VERSION 5.7 ;
  NOWIREEXTENSIONATPIN ON ;
  DIVIDERCHAR "/" ;
  BUSBITCHARS "[]" ;
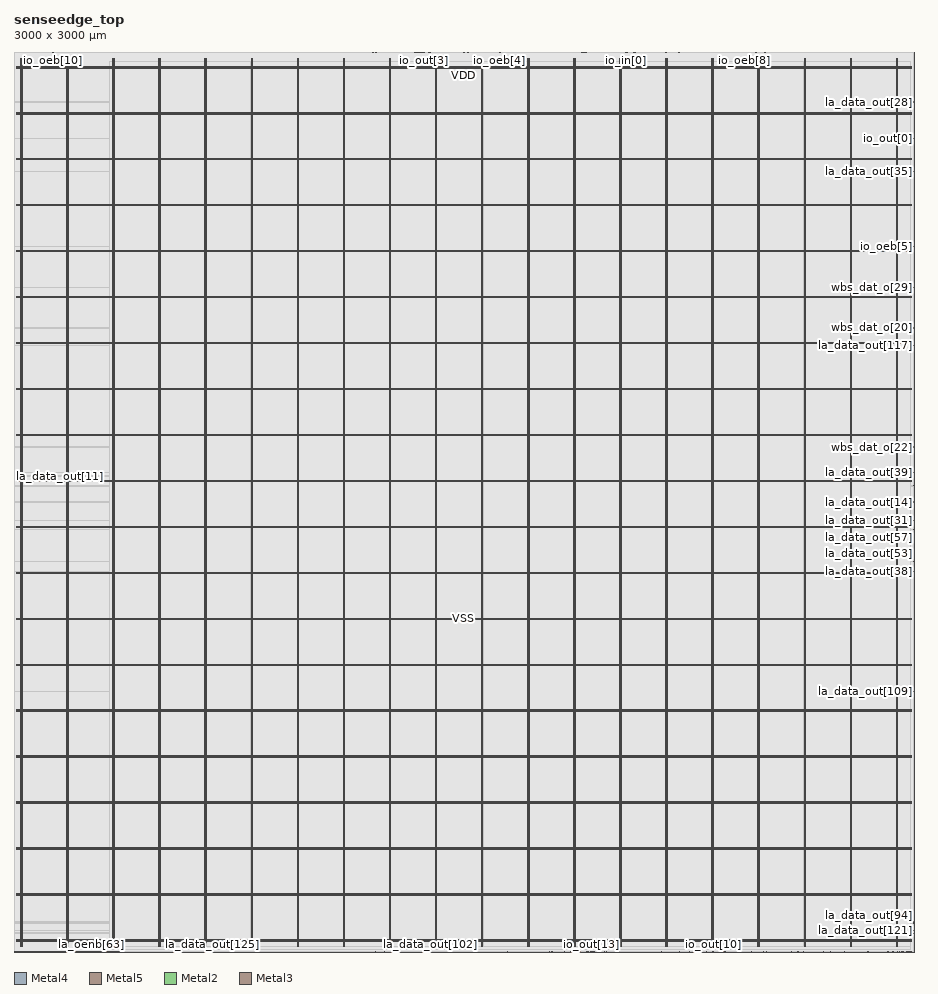
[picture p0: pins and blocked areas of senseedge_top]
MACRO senseedge_top
  CLASS BLOCK ;
  FOREIGN senseedge_top ;
  ORIGIN 0.000 0.000 ;
  SIZE 3000.000 BY 3000.000 ;
  PIN VDD
    DIRECTION INOUT ;
    USE POWER ;
    PORT
      LAYER Metal4 ;
        RECT 22.240 19.860 23.840 2978.940 ;
    END
    PORT
      LAYER Metal4 ;
        RECT 175.840 19.860 177.440 2978.940 ;
    END
    PORT
      LAYER Metal4 ;
        RECT 329.440 19.860 331.040 2978.940 ;
    END
    PORT
      LAYER Metal4 ;
        RECT 483.040 19.860 484.640 2978.940 ;
    END
    PORT
      LAYER Metal4 ;
        RECT 636.640 19.860 638.240 2978.940 ;
    END
    PORT
      LAYER Metal4 ;
        RECT 790.240 19.860 791.840 2978.940 ;
    END
    PORT
      LAYER Metal4 ;
        RECT 943.840 19.860 945.440 2978.940 ;
    END
    PORT
      LAYER Metal4 ;
        RECT 1097.440 19.860 1099.040 2978.940 ;
    END
    PORT
      LAYER Metal4 ;
        RECT 1251.040 19.860 1252.640 2978.940 ;
    END
    PORT
      LAYER Metal4 ;
        RECT 1404.640 19.860 1406.240 2978.940 ;
    END
    PORT
      LAYER Metal4 ;
        RECT 1558.240 19.860 1559.840 2978.940 ;
    END
    PORT
      LAYER Metal4 ;
        RECT 1711.840 19.860 1713.440 2978.940 ;
    END
    PORT
      LAYER Metal4 ;
        RECT 1865.440 19.860 1867.040 2978.940 ;
    END
    PORT
      LAYER Metal4 ;
        RECT 2019.040 19.860 2020.640 2978.940 ;
    END
    PORT
      LAYER Metal4 ;
        RECT 2172.640 19.860 2174.240 2978.940 ;
    END
    PORT
      LAYER Metal4 ;
        RECT 2326.240 19.860 2327.840 2978.940 ;
    END
    PORT
      LAYER Metal4 ;
        RECT 2479.840 19.860 2481.440 2978.940 ;
    END
    PORT
      LAYER Metal4 ;
        RECT 2633.440 19.860 2635.040 2978.940 ;
    END
    PORT
      LAYER Metal4 ;
        RECT 2787.040 19.860 2788.640 2978.940 ;
    END
    PORT
      LAYER Metal4 ;
        RECT 2940.640 19.860 2942.240 2978.940 ;
    END
    PORT
      LAYER Metal5 ;
        RECT 6.720 36.010 2993.200 37.610 ;
    END
    PORT
      LAYER Metal5 ;
        RECT 6.720 189.190 2993.200 190.790 ;
    END
    PORT
      LAYER Metal5 ;
        RECT 6.720 342.370 2993.200 343.970 ;
    END
    PORT
      LAYER Metal5 ;
        RECT 6.720 495.550 2993.200 497.150 ;
    END
    PORT
      LAYER Metal5 ;
        RECT 6.720 648.730 2993.200 650.330 ;
    END
    PORT
      LAYER Metal5 ;
        RECT 6.720 801.910 2993.200 803.510 ;
    END
    PORT
      LAYER Metal5 ;
        RECT 6.720 955.090 2993.200 956.690 ;
    END
    PORT
      LAYER Metal5 ;
        RECT 6.720 1108.270 2993.200 1109.870 ;
    END
    PORT
      LAYER Metal5 ;
        RECT 6.720 1261.450 2993.200 1263.050 ;
    END
    PORT
      LAYER Metal5 ;
        RECT 6.720 1414.630 2993.200 1416.230 ;
    END
    PORT
      LAYER Metal5 ;
        RECT 6.720 1567.810 2993.200 1569.410 ;
    END
    PORT
      LAYER Metal5 ;
        RECT 6.720 1720.990 2993.200 1722.590 ;
    END
    PORT
      LAYER Metal5 ;
        RECT 6.720 1874.170 2993.200 1875.770 ;
    END
    PORT
      LAYER Metal5 ;
        RECT 6.720 2027.350 2993.200 2028.950 ;
    END
    PORT
      LAYER Metal5 ;
        RECT 6.720 2180.530 2993.200 2182.130 ;
    END
    PORT
      LAYER Metal5 ;
        RECT 6.720 2333.710 2993.200 2335.310 ;
    END
    PORT
      LAYER Metal5 ;
        RECT 6.720 2486.890 2993.200 2488.490 ;
    END
    PORT
      LAYER Metal5 ;
        RECT 6.720 2640.070 2993.200 2641.670 ;
    END
    PORT
      LAYER Metal5 ;
        RECT 6.720 2793.250 2993.200 2794.850 ;
    END
    PORT
      LAYER Metal5 ;
        RECT 6.720 2946.430 2993.200 2948.030 ;
    END
  END VDD
  PIN VSS
    DIRECTION INOUT ;
    USE GROUND ;
    PORT
      LAYER Metal4 ;
        RECT 25.540 19.860 27.140 2978.940 ;
    END
    PORT
      LAYER Metal4 ;
        RECT 179.140 19.860 180.740 2978.940 ;
    END
    PORT
      LAYER Metal4 ;
        RECT 332.740 19.860 334.340 2978.940 ;
    END
    PORT
      LAYER Metal4 ;
        RECT 486.340 19.860 487.940 2978.940 ;
    END
    PORT
      LAYER Metal4 ;
        RECT 639.940 19.860 641.540 2978.940 ;
    END
    PORT
      LAYER Metal4 ;
        RECT 793.540 19.860 795.140 2978.940 ;
    END
    PORT
      LAYER Metal4 ;
        RECT 947.140 19.860 948.740 2978.940 ;
    END
    PORT
      LAYER Metal4 ;
        RECT 1100.740 19.860 1102.340 2978.940 ;
    END
    PORT
      LAYER Metal4 ;
        RECT 1254.340 19.860 1255.940 2978.940 ;
    END
    PORT
      LAYER Metal4 ;
        RECT 1407.940 19.860 1409.540 2978.940 ;
    END
    PORT
      LAYER Metal4 ;
        RECT 1561.540 19.860 1563.140 2978.940 ;
    END
    PORT
      LAYER Metal4 ;
        RECT 1715.140 19.860 1716.740 2978.940 ;
    END
    PORT
      LAYER Metal4 ;
        RECT 1868.740 19.860 1870.340 2978.940 ;
    END
    PORT
      LAYER Metal4 ;
        RECT 2022.340 19.860 2023.940 2978.940 ;
    END
    PORT
      LAYER Metal4 ;
        RECT 2175.940 19.860 2177.540 2978.940 ;
    END
    PORT
      LAYER Metal4 ;
        RECT 2329.540 19.860 2331.140 2978.940 ;
    END
    PORT
      LAYER Metal4 ;
        RECT 2483.140 19.860 2484.740 2978.940 ;
    END
    PORT
      LAYER Metal4 ;
        RECT 2636.740 19.860 2638.340 2978.940 ;
    END
    PORT
      LAYER Metal4 ;
        RECT 2790.340 19.860 2791.940 2978.940 ;
    END
    PORT
      LAYER Metal4 ;
        RECT 2943.940 19.860 2945.540 2978.940 ;
    END
    PORT
      LAYER Metal5 ;
        RECT 6.720 39.310 2993.200 40.910 ;
    END
    PORT
      LAYER Metal5 ;
        RECT 6.720 192.490 2993.200 194.090 ;
    END
    PORT
      LAYER Metal5 ;
        RECT 6.720 345.670 2993.200 347.270 ;
    END
    PORT
      LAYER Metal5 ;
        RECT 6.720 498.850 2993.200 500.450 ;
    END
    PORT
      LAYER Metal5 ;
        RECT 6.720 652.030 2993.200 653.630 ;
    END
    PORT
      LAYER Metal5 ;
        RECT 6.720 805.210 2993.200 806.810 ;
    END
    PORT
      LAYER Metal5 ;
        RECT 6.720 958.390 2993.200 959.990 ;
    END
    PORT
      LAYER Metal5 ;
        RECT 6.720 1111.570 2993.200 1113.170 ;
    END
    PORT
      LAYER Metal5 ;
        RECT 6.720 1264.750 2993.200 1266.350 ;
    END
    PORT
      LAYER Metal5 ;
        RECT 6.720 1417.930 2993.200 1419.530 ;
    END
    PORT
      LAYER Metal5 ;
        RECT 6.720 1571.110 2993.200 1572.710 ;
    END
    PORT
      LAYER Metal5 ;
        RECT 6.720 1724.290 2993.200 1725.890 ;
    END
    PORT
      LAYER Metal5 ;
        RECT 6.720 1877.470 2993.200 1879.070 ;
    END
    PORT
      LAYER Metal5 ;
        RECT 6.720 2030.650 2993.200 2032.250 ;
    END
    PORT
      LAYER Metal5 ;
        RECT 6.720 2183.830 2993.200 2185.430 ;
    END
    PORT
      LAYER Metal5 ;
        RECT 6.720 2337.010 2993.200 2338.610 ;
    END
    PORT
      LAYER Metal5 ;
        RECT 6.720 2490.190 2993.200 2491.790 ;
    END
    PORT
      LAYER Metal5 ;
        RECT 6.720 2643.370 2993.200 2644.970 ;
    END
    PORT
      LAYER Metal5 ;
        RECT 6.720 2796.550 2993.200 2798.150 ;
    END
    PORT
      LAYER Metal5 ;
        RECT 6.720 2949.730 2993.200 2951.330 ;
    END
  END VSS
  PIN io_in[0]
    DIRECTION INPUT ;
    USE SIGNAL ;
    ANTENNAGATEAREA 0.396000 ;
    PORT
      LAYER Metal2 ;
        RECT 2039.520 2999.440 2040.080 3000.000 ;
    END
  END io_in[0]
  PIN io_in[10]
    DIRECTION INPUT ;
    USE SIGNAL ;
    PORT
      LAYER Metal2 ;
        RECT 1.120 0.000 1.680 0.560 ;
    END
  END io_in[10]
  PIN io_in[11]
    DIRECTION INPUT ;
    USE SIGNAL ;
    PORT
      LAYER Metal2 ;
        RECT 2.240 0.000 2.800 0.560 ;
    END
  END io_in[11]
  PIN io_in[12]
    DIRECTION INPUT ;
    USE SIGNAL ;
    PORT
      LAYER Metal2 ;
        RECT 3.360 0.000 3.920 0.560 ;
    END
  END io_in[12]
  PIN io_in[13]
    DIRECTION INPUT ;
    USE SIGNAL ;
    PORT
      LAYER Metal2 ;
        RECT 4.480 0.000 5.040 0.560 ;
    END
  END io_in[13]
  PIN io_in[14]
    DIRECTION INPUT ;
    USE SIGNAL ;
    PORT
      LAYER Metal2 ;
        RECT 5.600 0.000 6.160 0.560 ;
    END
  END io_in[14]
  PIN io_in[15]
    DIRECTION INPUT ;
    USE SIGNAL ;
    PORT
      LAYER Metal2 ;
        RECT 6.720 0.000 7.280 0.560 ;
    END
  END io_in[15]
  PIN io_in[1]
    DIRECTION INPUT ;
    USE SIGNAL ;
    PORT
      LAYER Metal2 ;
        RECT 7.840 0.000 8.400 0.560 ;
    END
  END io_in[1]
  PIN io_in[2]
    DIRECTION INPUT ;
    USE SIGNAL ;
    PORT
      LAYER Metal2 ;
        RECT 8.960 0.000 9.520 0.560 ;
    END
  END io_in[2]
  PIN io_in[3]
    DIRECTION INPUT ;
    USE SIGNAL ;
    PORT
      LAYER Metal2 ;
        RECT 10.080 0.000 10.640 0.560 ;
    END
  END io_in[3]
  PIN io_in[4]
    DIRECTION INPUT ;
    USE SIGNAL ;
    PORT
      LAYER Metal2 ;
        RECT 11.200 0.000 11.760 0.560 ;
    END
  END io_in[4]
  PIN io_in[5]
    DIRECTION INPUT ;
    USE SIGNAL ;
    PORT
      LAYER Metal2 ;
        RECT 12.320 0.000 12.880 0.560 ;
    END
  END io_in[5]
  PIN io_in[6]
    DIRECTION INPUT ;
    USE SIGNAL ;
    PORT
      LAYER Metal2 ;
        RECT 13.440 0.000 14.000 0.560 ;
    END
  END io_in[6]
  PIN io_in[7]
    DIRECTION INPUT ;
    USE SIGNAL ;
    PORT
      LAYER Metal2 ;
        RECT 14.560 0.000 15.120 0.560 ;
    END
  END io_in[7]
  PIN io_in[8]
    DIRECTION INPUT ;
    USE SIGNAL ;
    PORT
      LAYER Metal2 ;
        RECT 15.680 0.000 16.240 0.560 ;
    END
  END io_in[8]
  PIN io_in[9]
    DIRECTION INPUT ;
    USE SIGNAL ;
    PORT
      LAYER Metal2 ;
        RECT 16.800 0.000 17.360 0.560 ;
    END
  END io_in[9]
  PIN io_oeb[0]
    DIRECTION OUTPUT ;
    USE SIGNAL ;
    ANTENNADIFFAREA 0.396000 ;
    PORT
      LAYER Metal2 ;
        RECT 2251.200 0.000 2251.760 0.560 ;
    END
  END io_oeb[0]
  PIN io_oeb[10]
    DIRECTION OUTPUT ;
    USE SIGNAL ;
    ANTENNADIFFAREA 0.396000 ;
    PORT
      LAYER Metal2 ;
        RECT 129.920 2999.440 130.480 3000.000 ;
    END
  END io_oeb[10]
  PIN io_oeb[11]
    DIRECTION OUTPUT ;
    USE SIGNAL ;
    ANTENNADIFFAREA 0.396000 ;
    PORT
      LAYER Metal2 ;
        RECT 1933.120 0.000 1933.680 0.560 ;
    END
  END io_oeb[11]
  PIN io_oeb[12]
    DIRECTION OUTPUT ;
    USE SIGNAL ;
    ANTENNADIFFAREA 0.396000 ;
    PORT
      LAYER Metal2 ;
        RECT 2117.920 2999.440 2118.480 3000.000 ;
    END
  END io_oeb[12]
  PIN io_oeb[13]
    DIRECTION OUTPUT ;
    USE SIGNAL ;
    ANTENNADIFFAREA 0.396000 ;
    PORT
      LAYER Metal2 ;
        RECT 1911.840 0.000 1912.400 0.560 ;
    END
  END io_oeb[13]
  PIN io_oeb[14]
    DIRECTION OUTPUT ;
    USE SIGNAL ;
    ANTENNADIFFAREA 0.396000 ;
    PORT
      LAYER Metal3 ;
        RECT 2999.440 62.720 3000.000 63.280 ;
    END
  END io_oeb[14]
  PIN io_oeb[15]
    DIRECTION OUTPUT ;
    USE SIGNAL ;
    ANTENNADIFFAREA 0.396000 ;
    PORT
      LAYER Metal2 ;
        RECT 2391.200 2999.440 2391.760 3000.000 ;
    END
  END io_oeb[15]
  PIN io_oeb[1]
    DIRECTION OUTPUT ;
    USE SIGNAL ;
    ANTENNADIFFAREA 0.290400 ;
    PORT
      LAYER Metal2 ;
        RECT 2051.840 2999.440 2052.400 3000.000 ;
    END
  END io_oeb[1]
  PIN io_oeb[2]
    DIRECTION OUTPUT ;
    USE SIGNAL ;
    ANTENNADIFFAREA 0.290400 ;
    PORT
      LAYER Metal2 ;
        RECT 2973.600 0.000 2974.160 0.560 ;
    END
  END io_oeb[2]
  PIN io_oeb[3]
    DIRECTION OUTPUT ;
    USE SIGNAL ;
    ANTENNADIFFAREA 0.290400 ;
    PORT
      LAYER Metal2 ;
        RECT 2115.680 2999.440 2116.240 3000.000 ;
    END
  END io_oeb[3]
  PIN io_oeb[4]
    DIRECTION OUTPUT ;
    USE SIGNAL ;
    ANTENNADIFFAREA 0.290400 ;
    PORT
      LAYER Metal2 ;
        RECT 1617.280 2999.440 1617.840 3000.000 ;
    END
  END io_oeb[4]
  PIN io_oeb[5]
    DIRECTION OUTPUT ;
    USE SIGNAL ;
    ANTENNADIFFAREA 0.290400 ;
    PORT
      LAYER Metal3 ;
        RECT 2999.440 2352.000 3000.000 2352.560 ;
    END
  END io_oeb[5]
  PIN io_oeb[6]
    DIRECTION OUTPUT ;
    USE SIGNAL ;
    ANTENNADIFFAREA 0.396000 ;
    PORT
      LAYER Metal2 ;
        RECT 2042.880 2999.440 2043.440 3000.000 ;
    END
  END io_oeb[6]
  PIN io_oeb[7]
    DIRECTION OUTPUT ;
    USE SIGNAL ;
    ANTENNADIFFAREA 0.396000 ;
    PORT
      LAYER Metal2 ;
        RECT 2951.200 0.000 2951.760 0.560 ;
    END
  END io_oeb[7]
  PIN io_oeb[8]
    DIRECTION OUTPUT ;
    USE SIGNAL ;
    ANTENNADIFFAREA 0.396000 ;
    PORT
      LAYER Metal2 ;
        RECT 2434.880 2999.440 2435.440 3000.000 ;
    END
  END io_oeb[8]
  PIN io_oeb[9]
    DIRECTION OUTPUT ;
    USE SIGNAL ;
    ANTENNADIFFAREA 0.396000 ;
    PORT
      LAYER Metal2 ;
        RECT 1972.320 2999.440 1972.880 3000.000 ;
    END
  END io_oeb[9]
  PIN io_out[0]
    DIRECTION OUTPUT ;
    USE SIGNAL ;
    ANTENNADIFFAREA 0.290400 ;
    PORT
      LAYER Metal3 ;
        RECT 2999.440 2711.520 3000.000 2712.080 ;
    END
  END io_out[0]
  PIN io_out[10]
    DIRECTION OUTPUT ;
    USE SIGNAL ;
    ANTENNADIFFAREA 0.290400 ;
    PORT
      LAYER Metal2 ;
        RECT 2331.840 0.000 2332.400 0.560 ;
    END
  END io_out[10]
  PIN io_out[11]
    DIRECTION OUTPUT ;
    USE SIGNAL ;
    ANTENNADIFFAREA 0.290400 ;
    PORT
      LAYER Metal2 ;
        RECT 2294.880 2999.440 2295.440 3000.000 ;
    END
  END io_out[11]
  PIN io_out[12]
    DIRECTION OUTPUT ;
    USE SIGNAL ;
    ANTENNADIFFAREA 0.290400 ;
    PORT
      LAYER Metal2 ;
        RECT 2157.120 0.000 2157.680 0.560 ;
    END
  END io_out[12]
  PIN io_out[13]
    DIRECTION OUTPUT ;
    USE SIGNAL ;
    ANTENNADIFFAREA 0.290400 ;
    PORT
      LAYER Metal2 ;
        RECT 1924.160 0.000 1924.720 0.560 ;
    END
  END io_out[13]
  PIN io_out[14]
    DIRECTION OUTPUT ;
    USE SIGNAL ;
    ANTENNADIFFAREA 0.290400 ;
    PORT
      LAYER Metal2 ;
        RECT 1888.320 0.000 1888.880 0.560 ;
    END
  END io_out[14]
  PIN io_out[15]
    DIRECTION OUTPUT ;
    USE SIGNAL ;
    ANTENNADIFFAREA 0.290400 ;
    PORT
      LAYER Metal2 ;
        RECT 1785.280 0.000 1785.840 0.560 ;
    END
  END io_out[15]
  PIN io_out[1]
    DIRECTION OUTPUT ;
    USE SIGNAL ;
    ANTENNADIFFAREA 1.386000 ;
    PORT
      LAYER Metal2 ;
        RECT 1681.120 2999.440 1681.680 3000.000 ;
    END
  END io_out[1]
  PIN io_out[2]
    DIRECTION OUTPUT ;
    USE SIGNAL ;
    ANTENNADIFFAREA 1.386000 ;
    PORT
      LAYER Metal2 ;
        RECT 1680.000 2999.440 1680.560 3000.000 ;
    END
  END io_out[2]
  PIN io_out[3]
    DIRECTION OUTPUT ;
    USE SIGNAL ;
    ANTENNADIFFAREA 1.386000 ;
    PORT
      LAYER Metal2 ;
        RECT 1365.280 2999.440 1365.840 3000.000 ;
    END
  END io_out[3]
  PIN io_out[4]
    DIRECTION OUTPUT ;
    USE SIGNAL ;
    ANTENNADIFFAREA 1.386000 ;
    PORT
      LAYER Metal2 ;
        RECT 1364.160 2999.440 1364.720 3000.000 ;
    END
  END io_out[4]
  PIN io_out[5]
    DIRECTION OUTPUT ;
    USE SIGNAL ;
    ANTENNADIFFAREA 0.396000 ;
    PORT
      LAYER Metal2 ;
        RECT 2698.080 0.000 2698.640 0.560 ;
    END
  END io_out[5]
  PIN io_out[6]
    DIRECTION OUTPUT ;
    USE SIGNAL ;
    ANTENNADIFFAREA 0.290400 ;
    PORT
      LAYER Metal2 ;
        RECT 2979.200 0.000 2979.760 0.560 ;
    END
  END io_out[6]
  PIN io_out[7]
    DIRECTION OUTPUT ;
    USE SIGNAL ;
    ANTENNADIFFAREA 0.290400 ;
    PORT
      LAYER Metal2 ;
        RECT 1974.560 0.000 1975.120 0.560 ;
    END
  END io_out[7]
  PIN io_out[8]
    DIRECTION OUTPUT ;
    USE SIGNAL ;
    ANTENNADIFFAREA 0.290400 ;
    PORT
      LAYER Metal2 ;
        RECT 2508.800 0.000 2509.360 0.560 ;
    END
  END io_out[8]
  PIN io_out[9]
    DIRECTION OUTPUT ;
    USE SIGNAL ;
    ANTENNADIFFAREA 0.290400 ;
    PORT
      LAYER Metal2 ;
        RECT 2990.400 0.000 2990.960 0.560 ;
    END
  END io_out[9]
  PIN irq[0]
    DIRECTION OUTPUT ;
    USE SIGNAL ;
    ANTENNADIFFAREA 1.386000 ;
    PORT
      LAYER Metal2 ;
        RECT 1344.000 2999.440 1344.560 3000.000 ;
    END
  END irq[0]
  PIN irq[1]
    DIRECTION OUTPUT ;
    USE SIGNAL ;
    ANTENNADIFFAREA 0.290400 ;
    PORT
      LAYER Metal2 ;
        RECT 1725.920 2999.440 1726.480 3000.000 ;
    END
  END irq[1]
  PIN irq[2]
    DIRECTION OUTPUT ;
    USE SIGNAL ;
    ANTENNADIFFAREA 0.290400 ;
    PORT
      LAYER Metal2 ;
        RECT 2985.920 0.000 2986.480 0.560 ;
    END
  END irq[2]
  PIN la_data_in[0]
    DIRECTION INPUT ;
    USE SIGNAL ;
    PORT
      LAYER Metal2 ;
        RECT 17.920 0.000 18.480 0.560 ;
    END
  END la_data_in[0]
  PIN la_data_in[100]
    DIRECTION INPUT ;
    USE SIGNAL ;
    PORT
      LAYER Metal2 ;
        RECT 19.040 0.000 19.600 0.560 ;
    END
  END la_data_in[100]
  PIN la_data_in[101]
    DIRECTION INPUT ;
    USE SIGNAL ;
    PORT
      LAYER Metal2 ;
        RECT 20.160 0.000 20.720 0.560 ;
    END
  END la_data_in[101]
  PIN la_data_in[102]
    DIRECTION INPUT ;
    USE SIGNAL ;
    PORT
      LAYER Metal2 ;
        RECT 21.280 0.000 21.840 0.560 ;
    END
  END la_data_in[102]
  PIN la_data_in[103]
    DIRECTION INPUT ;
    USE SIGNAL ;
    PORT
      LAYER Metal2 ;
        RECT 22.400 0.000 22.960 0.560 ;
    END
  END la_data_in[103]
  PIN la_data_in[104]
    DIRECTION INPUT ;
    USE SIGNAL ;
    PORT
      LAYER Metal2 ;
        RECT 23.520 0.000 24.080 0.560 ;
    END
  END la_data_in[104]
  PIN la_data_in[105]
    DIRECTION INPUT ;
    USE SIGNAL ;
    PORT
      LAYER Metal2 ;
        RECT 24.640 0.000 25.200 0.560 ;
    END
  END la_data_in[105]
  PIN la_data_in[106]
    DIRECTION INPUT ;
    USE SIGNAL ;
    PORT
      LAYER Metal2 ;
        RECT 25.760 0.000 26.320 0.560 ;
    END
  END la_data_in[106]
  PIN la_data_in[107]
    DIRECTION INPUT ;
    USE SIGNAL ;
    PORT
      LAYER Metal2 ;
        RECT 26.880 0.000 27.440 0.560 ;
    END
  END la_data_in[107]
  PIN la_data_in[108]
    DIRECTION INPUT ;
    USE SIGNAL ;
    PORT
      LAYER Metal2 ;
        RECT 28.000 0.000 28.560 0.560 ;
    END
  END la_data_in[108]
  PIN la_data_in[109]
    DIRECTION INPUT ;
    USE SIGNAL ;
    PORT
      LAYER Metal2 ;
        RECT 29.120 0.000 29.680 0.560 ;
    END
  END la_data_in[109]
  PIN la_data_in[10]
    DIRECTION INPUT ;
    USE SIGNAL ;
    PORT
      LAYER Metal2 ;
        RECT 30.240 0.000 30.800 0.560 ;
    END
  END la_data_in[10]
  PIN la_data_in[110]
    DIRECTION INPUT ;
    USE SIGNAL ;
    PORT
      LAYER Metal2 ;
        RECT 31.360 0.000 31.920 0.560 ;
    END
  END la_data_in[110]
  PIN la_data_in[111]
    DIRECTION INPUT ;
    USE SIGNAL ;
    PORT
      LAYER Metal2 ;
        RECT 32.480 0.000 33.040 0.560 ;
    END
  END la_data_in[111]
  PIN la_data_in[112]
    DIRECTION INPUT ;
    USE SIGNAL ;
    PORT
      LAYER Metal2 ;
        RECT 33.600 0.000 34.160 0.560 ;
    END
  END la_data_in[112]
  PIN la_data_in[113]
    DIRECTION INPUT ;
    USE SIGNAL ;
    PORT
      LAYER Metal2 ;
        RECT 34.720 0.000 35.280 0.560 ;
    END
  END la_data_in[113]
  PIN la_data_in[114]
    DIRECTION INPUT ;
    USE SIGNAL ;
    PORT
      LAYER Metal2 ;
        RECT 35.840 0.000 36.400 0.560 ;
    END
  END la_data_in[114]
  PIN la_data_in[115]
    DIRECTION INPUT ;
    USE SIGNAL ;
    PORT
      LAYER Metal2 ;
        RECT 36.960 0.000 37.520 0.560 ;
    END
  END la_data_in[115]
  PIN la_data_in[116]
    DIRECTION INPUT ;
    USE SIGNAL ;
    PORT
      LAYER Metal2 ;
        RECT 38.080 0.000 38.640 0.560 ;
    END
  END la_data_in[116]
  PIN la_data_in[117]
    DIRECTION INPUT ;
    USE SIGNAL ;
    PORT
      LAYER Metal2 ;
        RECT 39.200 0.000 39.760 0.560 ;
    END
  END la_data_in[117]
  PIN la_data_in[118]
    DIRECTION INPUT ;
    USE SIGNAL ;
    PORT
      LAYER Metal2 ;
        RECT 40.320 0.000 40.880 0.560 ;
    END
  END la_data_in[118]
  PIN la_data_in[119]
    DIRECTION INPUT ;
    USE SIGNAL ;
    PORT
      LAYER Metal2 ;
        RECT 41.440 0.000 42.000 0.560 ;
    END
  END la_data_in[119]
  PIN la_data_in[11]
    DIRECTION INPUT ;
    USE SIGNAL ;
    PORT
      LAYER Metal2 ;
        RECT 42.560 0.000 43.120 0.560 ;
    END
  END la_data_in[11]
  PIN la_data_in[120]
    DIRECTION INPUT ;
    USE SIGNAL ;
    PORT
      LAYER Metal2 ;
        RECT 43.680 0.000 44.240 0.560 ;
    END
  END la_data_in[120]
  PIN la_data_in[121]
    DIRECTION INPUT ;
    USE SIGNAL ;
    PORT
      LAYER Metal2 ;
        RECT 44.800 0.000 45.360 0.560 ;
    END
  END la_data_in[121]
  PIN la_data_in[122]
    DIRECTION INPUT ;
    USE SIGNAL ;
    PORT
      LAYER Metal2 ;
        RECT 45.920 0.000 46.480 0.560 ;
    END
  END la_data_in[122]
  PIN la_data_in[123]
    DIRECTION INPUT ;
    USE SIGNAL ;
    PORT
      LAYER Metal2 ;
        RECT 47.040 0.000 47.600 0.560 ;
    END
  END la_data_in[123]
  PIN la_data_in[124]
    DIRECTION INPUT ;
    USE SIGNAL ;
    PORT
      LAYER Metal2 ;
        RECT 48.160 0.000 48.720 0.560 ;
    END
  END la_data_in[124]
  PIN la_data_in[125]
    DIRECTION INPUT ;
    USE SIGNAL ;
    PORT
      LAYER Metal2 ;
        RECT 49.280 0.000 49.840 0.560 ;
    END
  END la_data_in[125]
  PIN la_data_in[126]
    DIRECTION INPUT ;
    USE SIGNAL ;
    PORT
      LAYER Metal2 ;
        RECT 50.400 0.000 50.960 0.560 ;
    END
  END la_data_in[126]
  PIN la_data_in[127]
    DIRECTION INPUT ;
    USE SIGNAL ;
    PORT
      LAYER Metal2 ;
        RECT 51.520 0.000 52.080 0.560 ;
    END
  END la_data_in[127]
  PIN la_data_in[12]
    DIRECTION INPUT ;
    USE SIGNAL ;
    PORT
      LAYER Metal2 ;
        RECT 52.640 0.000 53.200 0.560 ;
    END
  END la_data_in[12]
  PIN la_data_in[13]
    DIRECTION INPUT ;
    USE SIGNAL ;
    PORT
      LAYER Metal2 ;
        RECT 53.760 0.000 54.320 0.560 ;
    END
  END la_data_in[13]
  PIN la_data_in[14]
    DIRECTION INPUT ;
    USE SIGNAL ;
    PORT
      LAYER Metal2 ;
        RECT 54.880 0.000 55.440 0.560 ;
    END
  END la_data_in[14]
  PIN la_data_in[15]
    DIRECTION INPUT ;
    USE SIGNAL ;
    PORT
      LAYER Metal2 ;
        RECT 56.000 0.000 56.560 0.560 ;
    END
  END la_data_in[15]
  PIN la_data_in[16]
    DIRECTION INPUT ;
    USE SIGNAL ;
    PORT
      LAYER Metal2 ;
        RECT 57.120 0.000 57.680 0.560 ;
    END
  END la_data_in[16]
  PIN la_data_in[17]
    DIRECTION INPUT ;
    USE SIGNAL ;
    PORT
      LAYER Metal2 ;
        RECT 58.240 0.000 58.800 0.560 ;
    END
  END la_data_in[17]
  PIN la_data_in[18]
    DIRECTION INPUT ;
    USE SIGNAL ;
    PORT
      LAYER Metal2 ;
        RECT 59.360 0.000 59.920 0.560 ;
    END
  END la_data_in[18]
  PIN la_data_in[19]
    DIRECTION INPUT ;
    USE SIGNAL ;
    PORT
      LAYER Metal2 ;
        RECT 60.480 0.000 61.040 0.560 ;
    END
  END la_data_in[19]
  PIN la_data_in[1]
    DIRECTION INPUT ;
    USE SIGNAL ;
    PORT
      LAYER Metal2 ;
        RECT 61.600 0.000 62.160 0.560 ;
    END
  END la_data_in[1]
  PIN la_data_in[20]
    DIRECTION INPUT ;
    USE SIGNAL ;
    PORT
      LAYER Metal2 ;
        RECT 62.720 0.000 63.280 0.560 ;
    END
  END la_data_in[20]
  PIN la_data_in[21]
    DIRECTION INPUT ;
    USE SIGNAL ;
    PORT
      LAYER Metal2 ;
        RECT 63.840 0.000 64.400 0.560 ;
    END
  END la_data_in[21]
  PIN la_data_in[22]
    DIRECTION INPUT ;
    USE SIGNAL ;
    PORT
      LAYER Metal2 ;
        RECT 64.960 0.000 65.520 0.560 ;
    END
  END la_data_in[22]
  PIN la_data_in[23]
    DIRECTION INPUT ;
    USE SIGNAL ;
    PORT
      LAYER Metal2 ;
        RECT 66.080 0.000 66.640 0.560 ;
    END
  END la_data_in[23]
  PIN la_data_in[24]
    DIRECTION INPUT ;
    USE SIGNAL ;
    PORT
      LAYER Metal2 ;
        RECT 67.200 0.000 67.760 0.560 ;
    END
  END la_data_in[24]
  PIN la_data_in[25]
    DIRECTION INPUT ;
    USE SIGNAL ;
    PORT
      LAYER Metal2 ;
        RECT 68.320 0.000 68.880 0.560 ;
    END
  END la_data_in[25]
  PIN la_data_in[26]
    DIRECTION INPUT ;
    USE SIGNAL ;
    PORT
      LAYER Metal2 ;
        RECT 69.440 0.000 70.000 0.560 ;
    END
  END la_data_in[26]
  PIN la_data_in[27]
    DIRECTION INPUT ;
    USE SIGNAL ;
    PORT
      LAYER Metal2 ;
        RECT 70.560 0.000 71.120 0.560 ;
    END
  END la_data_in[27]
  PIN la_data_in[28]
    DIRECTION INPUT ;
    USE SIGNAL ;
    PORT
      LAYER Metal2 ;
        RECT 71.680 0.000 72.240 0.560 ;
    END
  END la_data_in[28]
  PIN la_data_in[29]
    DIRECTION INPUT ;
    USE SIGNAL ;
    PORT
      LAYER Metal2 ;
        RECT 72.800 0.000 73.360 0.560 ;
    END
  END la_data_in[29]
  PIN la_data_in[2]
    DIRECTION INPUT ;
    USE SIGNAL ;
    PORT
      LAYER Metal2 ;
        RECT 73.920 0.000 74.480 0.560 ;
    END
  END la_data_in[2]
  PIN la_data_in[30]
    DIRECTION INPUT ;
    USE SIGNAL ;
    PORT
      LAYER Metal2 ;
        RECT 75.040 0.000 75.600 0.560 ;
    END
  END la_data_in[30]
  PIN la_data_in[31]
    DIRECTION INPUT ;
    USE SIGNAL ;
    PORT
      LAYER Metal2 ;
        RECT 76.160 0.000 76.720 0.560 ;
    END
  END la_data_in[31]
  PIN la_data_in[32]
    DIRECTION INPUT ;
    USE SIGNAL ;
    PORT
      LAYER Metal2 ;
        RECT 77.280 0.000 77.840 0.560 ;
    END
  END la_data_in[32]
  PIN la_data_in[33]
    DIRECTION INPUT ;
    USE SIGNAL ;
    PORT
      LAYER Metal2 ;
        RECT 78.400 0.000 78.960 0.560 ;
    END
  END la_data_in[33]
  PIN la_data_in[34]
    DIRECTION INPUT ;
    USE SIGNAL ;
    PORT
      LAYER Metal2 ;
        RECT 79.520 0.000 80.080 0.560 ;
    END
  END la_data_in[34]
  PIN la_data_in[35]
    DIRECTION INPUT ;
    USE SIGNAL ;
    PORT
      LAYER Metal2 ;
        RECT 80.640 0.000 81.200 0.560 ;
    END
  END la_data_in[35]
  PIN la_data_in[36]
    DIRECTION INPUT ;
    USE SIGNAL ;
    PORT
      LAYER Metal2 ;
        RECT 81.760 0.000 82.320 0.560 ;
    END
  END la_data_in[36]
  PIN la_data_in[37]
    DIRECTION INPUT ;
    USE SIGNAL ;
    PORT
      LAYER Metal2 ;
        RECT 82.880 0.000 83.440 0.560 ;
    END
  END la_data_in[37]
  PIN la_data_in[38]
    DIRECTION INPUT ;
    USE SIGNAL ;
    PORT
      LAYER Metal2 ;
        RECT 84.000 0.000 84.560 0.560 ;
    END
  END la_data_in[38]
  PIN la_data_in[39]
    DIRECTION INPUT ;
    USE SIGNAL ;
    PORT
      LAYER Metal2 ;
        RECT 85.120 0.000 85.680 0.560 ;
    END
  END la_data_in[39]
  PIN la_data_in[3]
    DIRECTION INPUT ;
    USE SIGNAL ;
    PORT
      LAYER Metal2 ;
        RECT 86.240 0.000 86.800 0.560 ;
    END
  END la_data_in[3]
  PIN la_data_in[40]
    DIRECTION INPUT ;
    USE SIGNAL ;
    PORT
      LAYER Metal2 ;
        RECT 87.360 0.000 87.920 0.560 ;
    END
  END la_data_in[40]
  PIN la_data_in[41]
    DIRECTION INPUT ;
    USE SIGNAL ;
    PORT
      LAYER Metal2 ;
        RECT 88.480 0.000 89.040 0.560 ;
    END
  END la_data_in[41]
  PIN la_data_in[42]
    DIRECTION INPUT ;
    USE SIGNAL ;
    PORT
      LAYER Metal2 ;
        RECT 89.600 0.000 90.160 0.560 ;
    END
  END la_data_in[42]
  PIN la_data_in[43]
    DIRECTION INPUT ;
    USE SIGNAL ;
    PORT
      LAYER Metal2 ;
        RECT 90.720 0.000 91.280 0.560 ;
    END
  END la_data_in[43]
  PIN la_data_in[44]
    DIRECTION INPUT ;
    USE SIGNAL ;
    PORT
      LAYER Metal2 ;
        RECT 91.840 0.000 92.400 0.560 ;
    END
  END la_data_in[44]
  PIN la_data_in[45]
    DIRECTION INPUT ;
    USE SIGNAL ;
    PORT
      LAYER Metal2 ;
        RECT 92.960 0.000 93.520 0.560 ;
    END
  END la_data_in[45]
  PIN la_data_in[46]
    DIRECTION INPUT ;
    USE SIGNAL ;
    PORT
      LAYER Metal2 ;
        RECT 94.080 0.000 94.640 0.560 ;
    END
  END la_data_in[46]
  PIN la_data_in[47]
    DIRECTION INPUT ;
    USE SIGNAL ;
    PORT
      LAYER Metal2 ;
        RECT 95.200 0.000 95.760 0.560 ;
    END
  END la_data_in[47]
  PIN la_data_in[48]
    DIRECTION INPUT ;
    USE SIGNAL ;
    PORT
      LAYER Metal2 ;
        RECT 96.320 0.000 96.880 0.560 ;
    END
  END la_data_in[48]
  PIN la_data_in[49]
    DIRECTION INPUT ;
    USE SIGNAL ;
    PORT
      LAYER Metal2 ;
        RECT 97.440 0.000 98.000 0.560 ;
    END
  END la_data_in[49]
  PIN la_data_in[4]
    DIRECTION INPUT ;
    USE SIGNAL ;
    PORT
      LAYER Metal2 ;
        RECT 98.560 0.000 99.120 0.560 ;
    END
  END la_data_in[4]
  PIN la_data_in[50]
    DIRECTION INPUT ;
    USE SIGNAL ;
    PORT
      LAYER Metal2 ;
        RECT 99.680 0.000 100.240 0.560 ;
    END
  END la_data_in[50]
  PIN la_data_in[51]
    DIRECTION INPUT ;
    USE SIGNAL ;
    PORT
      LAYER Metal2 ;
        RECT 100.800 0.000 101.360 0.560 ;
    END
  END la_data_in[51]
  PIN la_data_in[52]
    DIRECTION INPUT ;
    USE SIGNAL ;
    PORT
      LAYER Metal2 ;
        RECT 101.920 0.000 102.480 0.560 ;
    END
  END la_data_in[52]
  PIN la_data_in[53]
    DIRECTION INPUT ;
    USE SIGNAL ;
    PORT
      LAYER Metal2 ;
        RECT 103.040 0.000 103.600 0.560 ;
    END
  END la_data_in[53]
  PIN la_data_in[54]
    DIRECTION INPUT ;
    USE SIGNAL ;
    PORT
      LAYER Metal2 ;
        RECT 104.160 0.000 104.720 0.560 ;
    END
  END la_data_in[54]
  PIN la_data_in[55]
    DIRECTION INPUT ;
    USE SIGNAL ;
    PORT
      LAYER Metal2 ;
        RECT 105.280 0.000 105.840 0.560 ;
    END
  END la_data_in[55]
  PIN la_data_in[56]
    DIRECTION INPUT ;
    USE SIGNAL ;
    PORT
      LAYER Metal2 ;
        RECT 106.400 0.000 106.960 0.560 ;
    END
  END la_data_in[56]
  PIN la_data_in[57]
    DIRECTION INPUT ;
    USE SIGNAL ;
    PORT
      LAYER Metal2 ;
        RECT 107.520 0.000 108.080 0.560 ;
    END
  END la_data_in[57]
  PIN la_data_in[58]
    DIRECTION INPUT ;
    USE SIGNAL ;
    PORT
      LAYER Metal2 ;
        RECT 108.640 0.000 109.200 0.560 ;
    END
  END la_data_in[58]
  PIN la_data_in[59]
    DIRECTION INPUT ;
    USE SIGNAL ;
    PORT
      LAYER Metal2 ;
        RECT 109.760 0.000 110.320 0.560 ;
    END
  END la_data_in[59]
  PIN la_data_in[5]
    DIRECTION INPUT ;
    USE SIGNAL ;
    PORT
      LAYER Metal2 ;
        RECT 110.880 0.000 111.440 0.560 ;
    END
  END la_data_in[5]
  PIN la_data_in[60]
    DIRECTION INPUT ;
    USE SIGNAL ;
    PORT
      LAYER Metal2 ;
        RECT 112.000 0.000 112.560 0.560 ;
    END
  END la_data_in[60]
  PIN la_data_in[61]
    DIRECTION INPUT ;
    USE SIGNAL ;
    PORT
      LAYER Metal2 ;
        RECT 113.120 0.000 113.680 0.560 ;
    END
  END la_data_in[61]
  PIN la_data_in[62]
    DIRECTION INPUT ;
    USE SIGNAL ;
    PORT
      LAYER Metal2 ;
        RECT 114.240 0.000 114.800 0.560 ;
    END
  END la_data_in[62]
  PIN la_data_in[63]
    DIRECTION INPUT ;
    USE SIGNAL ;
    PORT
      LAYER Metal2 ;
        RECT 115.360 0.000 115.920 0.560 ;
    END
  END la_data_in[63]
  PIN la_data_in[64]
    DIRECTION INPUT ;
    USE SIGNAL ;
    PORT
      LAYER Metal2 ;
        RECT 116.480 0.000 117.040 0.560 ;
    END
  END la_data_in[64]
  PIN la_data_in[65]
    DIRECTION INPUT ;
    USE SIGNAL ;
    PORT
      LAYER Metal2 ;
        RECT 117.600 0.000 118.160 0.560 ;
    END
  END la_data_in[65]
  PIN la_data_in[66]
    DIRECTION INPUT ;
    USE SIGNAL ;
    PORT
      LAYER Metal2 ;
        RECT 118.720 0.000 119.280 0.560 ;
    END
  END la_data_in[66]
  PIN la_data_in[67]
    DIRECTION INPUT ;
    USE SIGNAL ;
    PORT
      LAYER Metal2 ;
        RECT 119.840 0.000 120.400 0.560 ;
    END
  END la_data_in[67]
  PIN la_data_in[68]
    DIRECTION INPUT ;
    USE SIGNAL ;
    PORT
      LAYER Metal2 ;
        RECT 120.960 0.000 121.520 0.560 ;
    END
  END la_data_in[68]
  PIN la_data_in[69]
    DIRECTION INPUT ;
    USE SIGNAL ;
    PORT
      LAYER Metal2 ;
        RECT 122.080 0.000 122.640 0.560 ;
    END
  END la_data_in[69]
  PIN la_data_in[6]
    DIRECTION INPUT ;
    USE SIGNAL ;
    PORT
      LAYER Metal2 ;
        RECT 123.200 0.000 123.760 0.560 ;
    END
  END la_data_in[6]
  PIN la_data_in[70]
    DIRECTION INPUT ;
    USE SIGNAL ;
    PORT
      LAYER Metal2 ;
        RECT 124.320 0.000 124.880 0.560 ;
    END
  END la_data_in[70]
  PIN la_data_in[71]
    DIRECTION INPUT ;
    USE SIGNAL ;
    PORT
      LAYER Metal2 ;
        RECT 125.440 0.000 126.000 0.560 ;
    END
  END la_data_in[71]
  PIN la_data_in[72]
    DIRECTION INPUT ;
    USE SIGNAL ;
    PORT
      LAYER Metal2 ;
        RECT 126.560 0.000 127.120 0.560 ;
    END
  END la_data_in[72]
  PIN la_data_in[73]
    DIRECTION INPUT ;
    USE SIGNAL ;
    PORT
      LAYER Metal2 ;
        RECT 127.680 0.000 128.240 0.560 ;
    END
  END la_data_in[73]
  PIN la_data_in[74]
    DIRECTION INPUT ;
    USE SIGNAL ;
    PORT
      LAYER Metal2 ;
        RECT 128.800 0.000 129.360 0.560 ;
    END
  END la_data_in[74]
  PIN la_data_in[75]
    DIRECTION INPUT ;
    USE SIGNAL ;
    PORT
      LAYER Metal2 ;
        RECT 129.920 0.000 130.480 0.560 ;
    END
  END la_data_in[75]
  PIN la_data_in[76]
    DIRECTION INPUT ;
    USE SIGNAL ;
    PORT
      LAYER Metal2 ;
        RECT 131.040 0.000 131.600 0.560 ;
    END
  END la_data_in[76]
  PIN la_data_in[77]
    DIRECTION INPUT ;
    USE SIGNAL ;
    PORT
      LAYER Metal2 ;
        RECT 132.160 0.000 132.720 0.560 ;
    END
  END la_data_in[77]
  PIN la_data_in[78]
    DIRECTION INPUT ;
    USE SIGNAL ;
    PORT
      LAYER Metal2 ;
        RECT 133.280 0.000 133.840 0.560 ;
    END
  END la_data_in[78]
  PIN la_data_in[79]
    DIRECTION INPUT ;
    USE SIGNAL ;
    PORT
      LAYER Metal2 ;
        RECT 134.400 0.000 134.960 0.560 ;
    END
  END la_data_in[79]
  PIN la_data_in[7]
    DIRECTION INPUT ;
    USE SIGNAL ;
    PORT
      LAYER Metal2 ;
        RECT 135.520 0.000 136.080 0.560 ;
    END
  END la_data_in[7]
  PIN la_data_in[80]
    DIRECTION INPUT ;
    USE SIGNAL ;
    PORT
      LAYER Metal2 ;
        RECT 136.640 0.000 137.200 0.560 ;
    END
  END la_data_in[80]
  PIN la_data_in[81]
    DIRECTION INPUT ;
    USE SIGNAL ;
    PORT
      LAYER Metal2 ;
        RECT 137.760 0.000 138.320 0.560 ;
    END
  END la_data_in[81]
  PIN la_data_in[82]
    DIRECTION INPUT ;
    USE SIGNAL ;
    PORT
      LAYER Metal2 ;
        RECT 138.880 0.000 139.440 0.560 ;
    END
  END la_data_in[82]
  PIN la_data_in[83]
    DIRECTION INPUT ;
    USE SIGNAL ;
    PORT
      LAYER Metal2 ;
        RECT 140.000 0.000 140.560 0.560 ;
    END
  END la_data_in[83]
  PIN la_data_in[84]
    DIRECTION INPUT ;
    USE SIGNAL ;
    PORT
      LAYER Metal2 ;
        RECT 141.120 0.000 141.680 0.560 ;
    END
  END la_data_in[84]
  PIN la_data_in[85]
    DIRECTION INPUT ;
    USE SIGNAL ;
    PORT
      LAYER Metal2 ;
        RECT 142.240 0.000 142.800 0.560 ;
    END
  END la_data_in[85]
  PIN la_data_in[86]
    DIRECTION INPUT ;
    USE SIGNAL ;
    PORT
      LAYER Metal2 ;
        RECT 143.360 0.000 143.920 0.560 ;
    END
  END la_data_in[86]
  PIN la_data_in[87]
    DIRECTION INPUT ;
    USE SIGNAL ;
    PORT
      LAYER Metal2 ;
        RECT 144.480 0.000 145.040 0.560 ;
    END
  END la_data_in[87]
  PIN la_data_in[88]
    DIRECTION INPUT ;
    USE SIGNAL ;
    PORT
      LAYER Metal2 ;
        RECT 145.600 0.000 146.160 0.560 ;
    END
  END la_data_in[88]
  PIN la_data_in[89]
    DIRECTION INPUT ;
    USE SIGNAL ;
    PORT
      LAYER Metal2 ;
        RECT 146.720 0.000 147.280 0.560 ;
    END
  END la_data_in[89]
  PIN la_data_in[8]
    DIRECTION INPUT ;
    USE SIGNAL ;
    PORT
      LAYER Metal2 ;
        RECT 147.840 0.000 148.400 0.560 ;
    END
  END la_data_in[8]
  PIN la_data_in[90]
    DIRECTION INPUT ;
    USE SIGNAL ;
    PORT
      LAYER Metal2 ;
        RECT 148.960 0.000 149.520 0.560 ;
    END
  END la_data_in[90]
  PIN la_data_in[91]
    DIRECTION INPUT ;
    USE SIGNAL ;
    PORT
      LAYER Metal2 ;
        RECT 150.080 0.000 150.640 0.560 ;
    END
  END la_data_in[91]
  PIN la_data_in[92]
    DIRECTION INPUT ;
    USE SIGNAL ;
    PORT
      LAYER Metal2 ;
        RECT 151.200 0.000 151.760 0.560 ;
    END
  END la_data_in[92]
  PIN la_data_in[93]
    DIRECTION INPUT ;
    USE SIGNAL ;
    PORT
      LAYER Metal2 ;
        RECT 152.320 0.000 152.880 0.560 ;
    END
  END la_data_in[93]
  PIN la_data_in[94]
    DIRECTION INPUT ;
    USE SIGNAL ;
    PORT
      LAYER Metal2 ;
        RECT 153.440 0.000 154.000 0.560 ;
    END
  END la_data_in[94]
  PIN la_data_in[95]
    DIRECTION INPUT ;
    USE SIGNAL ;
    PORT
      LAYER Metal2 ;
        RECT 154.560 0.000 155.120 0.560 ;
    END
  END la_data_in[95]
  PIN la_data_in[96]
    DIRECTION INPUT ;
    USE SIGNAL ;
    PORT
      LAYER Metal2 ;
        RECT 155.680 0.000 156.240 0.560 ;
    END
  END la_data_in[96]
  PIN la_data_in[97]
    DIRECTION INPUT ;
    USE SIGNAL ;
    PORT
      LAYER Metal2 ;
        RECT 156.800 0.000 157.360 0.560 ;
    END
  END la_data_in[97]
  PIN la_data_in[98]
    DIRECTION INPUT ;
    USE SIGNAL ;
    PORT
      LAYER Metal2 ;
        RECT 157.920 0.000 158.480 0.560 ;
    END
  END la_data_in[98]
  PIN la_data_in[99]
    DIRECTION INPUT ;
    USE SIGNAL ;
    PORT
      LAYER Metal2 ;
        RECT 159.040 0.000 159.600 0.560 ;
    END
  END la_data_in[99]
  PIN la_data_in[9]
    DIRECTION INPUT ;
    USE SIGNAL ;
    PORT
      LAYER Metal2 ;
        RECT 160.160 0.000 160.720 0.560 ;
    END
  END la_data_in[9]
  PIN la_data_out[0]
    DIRECTION OUTPUT ;
    USE SIGNAL ;
    ANTENNADIFFAREA 1.386000 ;
    PORT
      LAYER Metal2 ;
        RECT 1576.960 2999.440 1577.520 3000.000 ;
    END
  END la_data_out[0]
  PIN la_data_out[100]
    DIRECTION OUTPUT ;
    USE SIGNAL ;
    ANTENNADIFFAREA 0.290400 ;
    PORT
      LAYER Metal2 ;
        RECT 2944.480 0.000 2945.040 0.560 ;
    END
  END la_data_out[100]
  PIN la_data_out[101]
    DIRECTION OUTPUT ;
    USE SIGNAL ;
    ANTENNADIFFAREA 0.290400 ;
    PORT
      LAYER Metal2 ;
        RECT 1884.960 2999.440 1885.520 3000.000 ;
    END
  END la_data_out[101]
  PIN la_data_out[102]
    DIRECTION OUTPUT ;
    USE SIGNAL ;
    ANTENNADIFFAREA 0.290400 ;
    PORT
      LAYER Metal2 ;
        RECT 1387.680 0.000 1388.240 0.560 ;
    END
  END la_data_out[102]
  PIN la_data_out[103]
    DIRECTION OUTPUT ;
    USE SIGNAL ;
    ANTENNADIFFAREA 0.290400 ;
    PORT
      LAYER Metal2 ;
        RECT 1793.120 0.000 1793.680 0.560 ;
    END
  END la_data_out[103]
  PIN la_data_out[104]
    DIRECTION OUTPUT ;
    USE SIGNAL ;
    ANTENNADIFFAREA 0.290400 ;
    PORT
      LAYER Metal2 ;
        RECT 2204.160 2999.440 2204.720 3000.000 ;
    END
  END la_data_out[104]
  PIN la_data_out[105]
    DIRECTION OUTPUT ;
    USE SIGNAL ;
    ANTENNADIFFAREA 0.290400 ;
    PORT
      LAYER Metal3 ;
        RECT 2999.440 1683.360 3000.000 1683.920 ;
    END
  END la_data_out[105]
  PIN la_data_out[106]
    DIRECTION OUTPUT ;
    USE SIGNAL ;
    ANTENNADIFFAREA 0.290400 ;
    PORT
      LAYER Metal2 ;
        RECT 1687.840 2999.440 1688.400 3000.000 ;
    END
  END la_data_out[106]
  PIN la_data_out[107]
    DIRECTION OUTPUT ;
    USE SIGNAL ;
    ANTENNADIFFAREA 0.290400 ;
    PORT
      LAYER Metal3 ;
        RECT 2999.440 2834.720 3000.000 2835.280 ;
    END
  END la_data_out[107]
  PIN la_data_out[108]
    DIRECTION OUTPUT ;
    USE SIGNAL ;
    ANTENNADIFFAREA 0.290400 ;
    PORT
      LAYER Metal2 ;
        RECT 2369.920 0.000 2370.480 0.560 ;
    END
  END la_data_out[108]
  PIN la_data_out[109]
    DIRECTION OUTPUT ;
    USE SIGNAL ;
    ANTENNADIFFAREA 0.290400 ;
    PORT
      LAYER Metal3 ;
        RECT 2999.440 869.120 3000.000 869.680 ;
    END
  END la_data_out[109]
  PIN la_data_out[10]
    DIRECTION OUTPUT ;
    USE SIGNAL ;
    ANTENNADIFFAREA 1.386000 ;
    PORT
      LAYER Metal2 ;
        RECT 1366.400 2999.440 1366.960 3000.000 ;
    END
  END la_data_out[10]
  PIN la_data_out[110]
    DIRECTION OUTPUT ;
    USE SIGNAL ;
    ANTENNADIFFAREA 0.290400 ;
    PORT
      LAYER Metal2 ;
        RECT 2317.280 2999.440 2317.840 3000.000 ;
    END
  END la_data_out[110]
  PIN la_data_out[111]
    DIRECTION OUTPUT ;
    USE SIGNAL ;
    ANTENNADIFFAREA 0.290400 ;
    PORT
      LAYER Metal2 ;
        RECT 2328.480 0.000 2329.040 0.560 ;
    END
  END la_data_out[111]
  PIN la_data_out[112]
    DIRECTION OUTPUT ;
    USE SIGNAL ;
    ANTENNADIFFAREA 0.290400 ;
    PORT
      LAYER Metal2 ;
        RECT 2959.040 0.000 2959.600 0.560 ;
    END
  END la_data_out[112]
  PIN la_data_out[113]
    DIRECTION OUTPUT ;
    USE SIGNAL ;
    ANTENNADIFFAREA 0.290400 ;
    PORT
      LAYER Metal2 ;
        RECT 1869.280 2999.440 1869.840 3000.000 ;
    END
  END la_data_out[113]
  PIN la_data_out[114]
    DIRECTION OUTPUT ;
    USE SIGNAL ;
    ANTENNADIFFAREA 0.290400 ;
    PORT
      LAYER Metal2 ;
        RECT 2307.200 0.000 2307.760 0.560 ;
    END
  END la_data_out[114]
  PIN la_data_out[115]
    DIRECTION OUTPUT ;
    USE SIGNAL ;
    ANTENNADIFFAREA 0.290400 ;
    PORT
      LAYER Metal2 ;
        RECT 2217.600 0.000 2218.160 0.560 ;
    END
  END la_data_out[115]
  PIN la_data_out[116]
    DIRECTION OUTPUT ;
    USE SIGNAL ;
    ANTENNADIFFAREA 0.290400 ;
    PORT
      LAYER Metal2 ;
        RECT 2327.360 2999.440 2327.920 3000.000 ;
    END
  END la_data_out[116]
  PIN la_data_out[117]
    DIRECTION OUTPUT ;
    USE SIGNAL ;
    ANTENNADIFFAREA 0.290400 ;
    PORT
      LAYER Metal3 ;
        RECT 2999.440 2020.480 3000.000 2021.040 ;
    END
  END la_data_out[117]
  PIN la_data_out[118]
    DIRECTION OUTPUT ;
    USE SIGNAL ;
    ANTENNADIFFAREA 0.290400 ;
    PORT
      LAYER Metal2 ;
        RECT 2963.520 0.000 2964.080 0.560 ;
    END
  END la_data_out[118]
  PIN la_data_out[119]
    DIRECTION OUTPUT ;
    USE SIGNAL ;
    ANTENNADIFFAREA 0.290400 ;
    PORT
      LAYER Metal2 ;
        RECT 1834.560 0.000 1835.120 0.560 ;
    END
  END la_data_out[119]
  PIN la_data_out[11]
    DIRECTION OUTPUT ;
    USE SIGNAL ;
    ANTENNADIFFAREA 1.386000 ;
    PORT
      LAYER Metal3 ;
        RECT 0.000 1585.920 0.560 1586.480 ;
    END
  END la_data_out[11]
  PIN la_data_out[120]
    DIRECTION OUTPUT ;
    USE SIGNAL ;
    ANTENNADIFFAREA 0.290400 ;
    PORT
      LAYER Metal2 ;
        RECT 1982.400 2999.440 1982.960 3000.000 ;
    END
  END la_data_out[120]
  PIN la_data_out[121]
    DIRECTION OUTPUT ;
    USE SIGNAL ;
    ANTENNADIFFAREA 0.290400 ;
    PORT
      LAYER Metal3 ;
        RECT 2999.440 71.680 3000.000 72.240 ;
    END
  END la_data_out[121]
  PIN la_data_out[122]
    DIRECTION OUTPUT ;
    USE SIGNAL ;
    ANTENNADIFFAREA 0.290400 ;
    PORT
      LAYER Metal2 ;
        RECT 2472.960 2999.440 2473.520 3000.000 ;
    END
  END la_data_out[122]
  PIN la_data_out[123]
    DIRECTION OUTPUT ;
    USE SIGNAL ;
    ANTENNADIFFAREA 0.290400 ;
    PORT
      LAYER Metal2 ;
        RECT 2988.160 0.000 2988.720 0.560 ;
    END
  END la_data_out[123]
  PIN la_data_out[124]
    DIRECTION OUTPUT ;
    USE SIGNAL ;
    ANTENNADIFFAREA 0.290400 ;
    PORT
      LAYER Metal2 ;
        RECT 2767.520 0.000 2768.080 0.560 ;
    END
  END la_data_out[124]
  PIN la_data_out[125]
    DIRECTION OUTPUT ;
    USE SIGNAL ;
    ANTENNADIFFAREA 0.290400 ;
    PORT
      LAYER Metal2 ;
        RECT 661.920 0.000 662.480 0.560 ;
    END
  END la_data_out[125]
  PIN la_data_out[126]
    DIRECTION OUTPUT ;
    USE SIGNAL ;
    ANTENNADIFFAREA 0.290400 ;
    PORT
      LAYER Metal3 ;
        RECT 2999.440 60.480 3000.000 61.040 ;
    END
  END la_data_out[126]
  PIN la_data_out[127]
    DIRECTION OUTPUT ;
    USE SIGNAL ;
    ANTENNADIFFAREA 0.290400 ;
    PORT
      LAYER Metal2 ;
        RECT 2066.400 2999.440 2066.960 3000.000 ;
    END
  END la_data_out[127]
  PIN la_data_out[12]
    DIRECTION OUTPUT ;
    USE SIGNAL ;
    ANTENNADIFFAREA 1.386000 ;
    PORT
      LAYER Metal2 ;
        RECT 1347.360 2999.440 1347.920 3000.000 ;
    END
  END la_data_out[12]
  PIN la_data_out[13]
    DIRECTION OUTPUT ;
    USE SIGNAL ;
    ANTENNADIFFAREA 1.386000 ;
    PORT
      LAYER Metal2 ;
        RECT 1386.560 2999.440 1387.120 3000.000 ;
    END
  END la_data_out[13]
  PIN la_data_out[14]
    DIRECTION OUTPUT ;
    USE SIGNAL ;
    ANTENNADIFFAREA 1.386000 ;
    PORT
      LAYER Metal3 ;
        RECT 2999.440 1499.680 3000.000 1500.240 ;
    END
  END la_data_out[14]
  PIN la_data_out[15]
    DIRECTION OUTPUT ;
    USE SIGNAL ;
    ANTENNADIFFAREA 1.386000 ;
    PORT
      LAYER Metal2 ;
        RECT 1445.920 2999.440 1446.480 3000.000 ;
    END
  END la_data_out[15]
  PIN la_data_out[16]
    DIRECTION OUTPUT ;
    USE SIGNAL ;
    ANTENNADIFFAREA 1.386000 ;
    PORT
      LAYER Metal2 ;
        RECT 2047.360 2999.440 2047.920 3000.000 ;
    END
  END la_data_out[16]
  PIN la_data_out[17]
    DIRECTION OUTPUT ;
    USE SIGNAL ;
    ANTENNADIFFAREA 1.386000 ;
    PORT
      LAYER Metal2 ;
        RECT 2060.800 2999.440 2061.360 3000.000 ;
    END
  END la_data_out[17]
  PIN la_data_out[18]
    DIRECTION OUTPUT ;
    USE SIGNAL ;
    ANTENNADIFFAREA 1.386000 ;
    PORT
      LAYER Metal2 ;
        RECT 2064.160 2999.440 2064.720 3000.000 ;
    END
  END la_data_out[18]
  PIN la_data_out[19]
    DIRECTION OUTPUT ;
    USE SIGNAL ;
    ANTENNADIFFAREA 1.386000 ;
    PORT
      LAYER Metal2 ;
        RECT 2069.760 2999.440 2070.320 3000.000 ;
    END
  END la_data_out[19]
  PIN la_data_out[1]
    DIRECTION OUTPUT ;
    USE SIGNAL ;
    ANTENNADIFFAREA 1.386000 ;
    PORT
      LAYER Metal2 ;
        RECT 1579.200 2999.440 1579.760 3000.000 ;
    END
  END la_data_out[1]
  PIN la_data_out[20]
    DIRECTION OUTPUT ;
    USE SIGNAL ;
    ANTENNADIFFAREA 1.386000 ;
    PORT
      LAYER Metal2 ;
        RECT 2072.000 2999.440 2072.560 3000.000 ;
    END
  END la_data_out[20]
  PIN la_data_out[21]
    DIRECTION OUTPUT ;
    USE SIGNAL ;
    ANTENNADIFFAREA 1.386000 ;
    PORT
      LAYER Metal2 ;
        RECT 2070.880 2999.440 2071.440 3000.000 ;
    END
  END la_data_out[21]
  PIN la_data_out[22]
    DIRECTION OUTPUT ;
    USE SIGNAL ;
    ANTENNADIFFAREA 1.386000 ;
    PORT
      LAYER Metal2 ;
        RECT 1778.560 2999.440 1779.120 3000.000 ;
    END
  END la_data_out[22]
  PIN la_data_out[23]
    DIRECTION OUTPUT ;
    USE SIGNAL ;
    ANTENNADIFFAREA 1.386000 ;
    PORT
      LAYER Metal2 ;
        RECT 1349.600 2999.440 1350.160 3000.000 ;
    END
  END la_data_out[23]
  PIN la_data_out[24]
    DIRECTION OUTPUT ;
    USE SIGNAL ;
    ANTENNADIFFAREA 0.290400 ;
    PORT
      LAYER Metal2 ;
        RECT 2180.640 2999.440 2181.200 3000.000 ;
    END
  END la_data_out[24]
  PIN la_data_out[25]
    DIRECTION OUTPUT ;
    USE SIGNAL ;
    ANTENNADIFFAREA 0.290400 ;
    PORT
      LAYER Metal2 ;
        RECT 2458.400 0.000 2458.960 0.560 ;
    END
  END la_data_out[25]
  PIN la_data_out[26]
    DIRECTION OUTPUT ;
    USE SIGNAL ;
    ANTENNADIFFAREA 0.290400 ;
    PORT
      LAYER Metal2 ;
        RECT 2610.720 0.000 2611.280 0.560 ;
    END
  END la_data_out[26]
  PIN la_data_out[27]
    DIRECTION OUTPUT ;
    USE SIGNAL ;
    ANTENNADIFFAREA 0.290400 ;
    PORT
      LAYER Metal2 ;
        RECT 1923.040 0.000 1923.600 0.560 ;
    END
  END la_data_out[27]
  PIN la_data_out[28]
    DIRECTION OUTPUT ;
    USE SIGNAL ;
    ANTENNADIFFAREA 0.290400 ;
    PORT
      LAYER Metal3 ;
        RECT 2999.440 2831.360 3000.000 2831.920 ;
    END
  END la_data_out[28]
  PIN la_data_out[29]
    DIRECTION OUTPUT ;
    USE SIGNAL ;
    ANTENNADIFFAREA 0.290400 ;
    PORT
      LAYER Metal2 ;
        RECT 1973.440 0.000 1974.000 0.560 ;
    END
  END la_data_out[29]
  PIN la_data_out[2]
    DIRECTION OUTPUT ;
    USE SIGNAL ;
    ANTENNADIFFAREA 1.386000 ;
    PORT
      LAYER Metal2 ;
        RECT 1430.240 2999.440 1430.800 3000.000 ;
    END
  END la_data_out[2]
  PIN la_data_out[30]
    DIRECTION OUTPUT ;
    USE SIGNAL ;
    ANTENNADIFFAREA 0.290400 ;
    PORT
      LAYER Metal2 ;
        RECT 1619.520 2999.440 1620.080 3000.000 ;
    END
  END la_data_out[30]
  PIN la_data_out[31]
    DIRECTION OUTPUT ;
    USE SIGNAL ;
    ANTENNADIFFAREA 0.290400 ;
    PORT
      LAYER Metal3 ;
        RECT 2999.440 1438.080 3000.000 1438.640 ;
    END
  END la_data_out[31]
  PIN la_data_out[32]
    DIRECTION OUTPUT ;
    USE SIGNAL ;
    ANTENNADIFFAREA 0.290400 ;
    PORT
      LAYER Metal2 ;
        RECT 1853.600 0.000 1854.160 0.560 ;
    END
  END la_data_out[32]
  PIN la_data_out[33]
    DIRECTION OUTPUT ;
    USE SIGNAL ;
    ANTENNADIFFAREA 0.290400 ;
    PORT
      LAYER Metal2 ;
        RECT 2269.120 2999.440 2269.680 3000.000 ;
    END
  END la_data_out[33]
  PIN la_data_out[34]
    DIRECTION OUTPUT ;
    USE SIGNAL ;
    ANTENNADIFFAREA 0.290400 ;
    PORT
      LAYER Metal2 ;
        RECT 1873.760 2999.440 1874.320 3000.000 ;
    END
  END la_data_out[34]
  PIN la_data_out[35]
    DIRECTION OUTPUT ;
    USE SIGNAL ;
    ANTENNADIFFAREA 0.290400 ;
    PORT
      LAYER Metal3 ;
        RECT 2999.440 2601.760 3000.000 2602.320 ;
    END
  END la_data_out[35]
  PIN la_data_out[36]
    DIRECTION OUTPUT ;
    USE SIGNAL ;
    ANTENNADIFFAREA 0.290400 ;
    PORT
      LAYER Metal2 ;
        RECT 1559.040 2999.440 1559.600 3000.000 ;
    END
  END la_data_out[36]
  PIN la_data_out[37]
    DIRECTION OUTPUT ;
    USE SIGNAL ;
    ANTENNADIFFAREA 0.290400 ;
    PORT
      LAYER Metal2 ;
        RECT 2981.440 0.000 2982.000 0.560 ;
    END
  END la_data_out[37]
  PIN la_data_out[38]
    DIRECTION OUTPUT ;
    USE SIGNAL ;
    ANTENNADIFFAREA 0.290400 ;
    PORT
      LAYER Metal3 ;
        RECT 2999.440 1268.960 3000.000 1269.520 ;
    END
  END la_data_out[38]
  PIN la_data_out[39]
    DIRECTION OUTPUT ;
    USE SIGNAL ;
    ANTENNADIFFAREA 0.290400 ;
    PORT
      LAYER Metal3 ;
        RECT 2999.440 1598.240 3000.000 1598.800 ;
    END
  END la_data_out[39]
  PIN la_data_out[3]
    DIRECTION OUTPUT ;
    USE SIGNAL ;
    ANTENNADIFFAREA 1.386000 ;
    PORT
      LAYER Metal2 ;
        RECT 1429.120 2999.440 1429.680 3000.000 ;
    END
  END la_data_out[3]
  PIN la_data_out[40]
    DIRECTION OUTPUT ;
    USE SIGNAL ;
    ANTENNADIFFAREA 0.290400 ;
    PORT
      LAYER Metal2 ;
        RECT 2416.960 0.000 2417.520 0.560 ;
    END
  END la_data_out[40]
  PIN la_data_out[41]
    DIRECTION OUTPUT ;
    USE SIGNAL ;
    ANTENNADIFFAREA 0.290400 ;
    PORT
      LAYER Metal2 ;
        RECT 1870.400 0.000 1870.960 0.560 ;
    END
  END la_data_out[41]
  PIN la_data_out[42]
    DIRECTION OUTPUT ;
    USE SIGNAL ;
    ANTENNADIFFAREA 0.290400 ;
    PORT
      LAYER Metal2 ;
        RECT 2843.680 0.000 2844.240 0.560 ;
    END
  END la_data_out[42]
  PIN la_data_out[43]
    DIRECTION OUTPUT ;
    USE SIGNAL ;
    ANTENNADIFFAREA 0.290400 ;
    PORT
      LAYER Metal2 ;
        RECT 2497.600 0.000 2498.160 0.560 ;
    END
  END la_data_out[43]
  PIN la_data_out[44]
    DIRECTION OUTPUT ;
    USE SIGNAL ;
    ANTENNADIFFAREA 0.290400 ;
    PORT
      LAYER Metal2 ;
        RECT 1683.360 2999.440 1683.920 3000.000 ;
    END
  END la_data_out[44]
  PIN la_data_out[45]
    DIRECTION OUTPUT ;
    USE SIGNAL ;
    ANTENNADIFFAREA 0.290400 ;
    PORT
      LAYER Metal2 ;
        RECT 2270.240 0.000 2270.800 0.560 ;
    END
  END la_data_out[45]
  PIN la_data_out[46]
    DIRECTION OUTPUT ;
    USE SIGNAL ;
    ANTENNADIFFAREA 0.290400 ;
    PORT
      LAYER Metal2 ;
        RECT 2927.680 0.000 2928.240 0.560 ;
    END
  END la_data_out[46]
  PIN la_data_out[47]
    DIRECTION OUTPUT ;
    USE SIGNAL ;
    ANTENNADIFFAREA 0.290400 ;
    PORT
      LAYER Metal2 ;
        RECT 2614.080 0.000 2614.640 0.560 ;
    END
  END la_data_out[47]
  PIN la_data_out[48]
    DIRECTION OUTPUT ;
    USE SIGNAL ;
    ANTENNADIFFAREA 0.290400 ;
    PORT
      LAYER Metal2 ;
        RECT 2365.440 0.000 2366.000 0.560 ;
    END
  END la_data_out[48]
  PIN la_data_out[49]
    DIRECTION OUTPUT ;
    USE SIGNAL ;
    ANTENNADIFFAREA 0.290400 ;
    PORT
      LAYER Metal2 ;
        RECT 2355.360 2999.440 2355.920 3000.000 ;
    END
  END la_data_out[49]
  PIN la_data_out[4]
    DIRECTION OUTPUT ;
    USE SIGNAL ;
    ANTENNADIFFAREA 1.386000 ;
    PORT
      LAYER Metal2 ;
        RECT 1428.000 2999.440 1428.560 3000.000 ;
    END
  END la_data_out[4]
  PIN la_data_out[50]
    DIRECTION OUTPUT ;
    USE SIGNAL ;
    ANTENNADIFFAREA 0.290400 ;
    PORT
      LAYER Metal2 ;
        RECT 2160.480 2999.440 2161.040 3000.000 ;
    END
  END la_data_out[50]
  PIN la_data_out[51]
    DIRECTION OUTPUT ;
    USE SIGNAL ;
    ANTENNADIFFAREA 0.290400 ;
    PORT
      LAYER Metal2 ;
        RECT 2960.160 0.000 2960.720 0.560 ;
    END
  END la_data_out[51]
  PIN la_data_out[52]
    DIRECTION OUTPUT ;
    USE SIGNAL ;
    ANTENNADIFFAREA 0.290400 ;
    PORT
      LAYER Metal2 ;
        RECT 2536.800 2999.440 2537.360 3000.000 ;
    END
  END la_data_out[52]
  PIN la_data_out[53]
    DIRECTION OUTPUT ;
    USE SIGNAL ;
    ANTENNADIFFAREA 0.290400 ;
    PORT
      LAYER Metal3 ;
        RECT 2999.440 1301.440 3000.000 1302.000 ;
    END
  END la_data_out[53]
  PIN la_data_out[54]
    DIRECTION OUTPUT ;
    USE SIGNAL ;
    ANTENNADIFFAREA 0.290400 ;
    PORT
      LAYER Metal2 ;
        RECT 2132.480 2999.440 2133.040 3000.000 ;
    END
  END la_data_out[54]
  PIN la_data_out[55]
    DIRECTION OUTPUT ;
    USE SIGNAL ;
    ANTENNADIFFAREA 0.290400 ;
    PORT
      LAYER Metal2 ;
        RECT 1899.520 2999.440 1900.080 3000.000 ;
    END
  END la_data_out[55]
  PIN la_data_out[56]
    DIRECTION OUTPUT ;
    USE SIGNAL ;
    ANTENNADIFFAREA 0.290400 ;
    PORT
      LAYER Metal2 ;
        RECT 2965.760 0.000 2966.320 0.560 ;
    END
  END la_data_out[56]
  PIN la_data_out[57]
    DIRECTION OUTPUT ;
    USE SIGNAL ;
    ANTENNADIFFAREA 0.290400 ;
    PORT
      LAYER Metal3 ;
        RECT 2999.440 1407.840 3000.000 1408.400 ;
    END
  END la_data_out[57]
  PIN la_data_out[58]
    DIRECTION OUTPUT ;
    USE SIGNAL ;
    ANTENNADIFFAREA 0.290400 ;
    PORT
      LAYER Metal2 ;
        RECT 2931.040 0.000 2931.600 0.560 ;
    END
  END la_data_out[58]
  PIN la_data_out[59]
    DIRECTION OUTPUT ;
    USE SIGNAL ;
    ANTENNADIFFAREA 0.290400 ;
    PORT
      LAYER Metal2 ;
        RECT 2507.680 2999.440 2508.240 3000.000 ;
    END
  END la_data_out[59]
  PIN la_data_out[5]
    DIRECTION OUTPUT ;
    USE SIGNAL ;
    ANTENNADIFFAREA 1.386000 ;
    PORT
      LAYER Metal2 ;
        RECT 1426.880 2999.440 1427.440 3000.000 ;
    END
  END la_data_out[5]
  PIN la_data_out[60]
    DIRECTION OUTPUT ;
    USE SIGNAL ;
    ANTENNADIFFAREA 0.290400 ;
    PORT
      LAYER Metal2 ;
        RECT 2158.240 0.000 2158.800 0.560 ;
    END
  END la_data_out[60]
  PIN la_data_out[61]
    DIRECTION OUTPUT ;
    USE SIGNAL ;
    ANTENNADIFFAREA 0.290400 ;
    PORT
      LAYER Metal2 ;
        RECT 1644.160 0.000 1644.720 0.560 ;
    END
  END la_data_out[61]
  PIN la_data_out[62]
    DIRECTION OUTPUT ;
    USE SIGNAL ;
    ANTENNADIFFAREA 0.290400 ;
    PORT
      LAYER Metal2 ;
        RECT 2153.760 2999.440 2154.320 3000.000 ;
    END
  END la_data_out[62]
  PIN la_data_out[63]
    DIRECTION OUTPUT ;
    USE SIGNAL ;
    ANTENNADIFFAREA 0.290400 ;
    PORT
      LAYER Metal2 ;
        RECT 1921.920 0.000 1922.480 0.560 ;
    END
  END la_data_out[63]
  PIN la_data_out[64]
    DIRECTION OUTPUT ;
    USE SIGNAL ;
    ANTENNADIFFAREA 0.290400 ;
    PORT
      LAYER Metal2 ;
        RECT 1912.960 0.000 1913.520 0.560 ;
    END
  END la_data_out[64]
  PIN la_data_out[65]
    DIRECTION OUTPUT ;
    USE SIGNAL ;
    ANTENNADIFFAREA 0.290400 ;
    PORT
      LAYER Metal2 ;
        RECT 2172.800 2999.440 2173.360 3000.000 ;
    END
  END la_data_out[65]
  PIN la_data_out[66]
    DIRECTION OUTPUT ;
    USE SIGNAL ;
    ANTENNADIFFAREA 0.290400 ;
    PORT
      LAYER Metal2 ;
        RECT 2162.720 2999.440 2163.280 3000.000 ;
    END
  END la_data_out[66]
  PIN la_data_out[67]
    DIRECTION OUTPUT ;
    USE SIGNAL ;
    ANTENNADIFFAREA 0.290400 ;
    PORT
      LAYER Metal2 ;
        RECT 2983.680 0.000 2984.240 0.560 ;
    END
  END la_data_out[67]
  PIN la_data_out[68]
    DIRECTION OUTPUT ;
    USE SIGNAL ;
    ANTENNADIFFAREA 0.290400 ;
    PORT
      LAYER Metal2 ;
        RECT 2386.720 2999.440 2387.280 3000.000 ;
    END
  END la_data_out[68]
  PIN la_data_out[69]
    DIRECTION OUTPUT ;
    USE SIGNAL ;
    ANTENNADIFFAREA 0.290400 ;
    PORT
      LAYER Metal2 ;
        RECT 2556.960 2999.440 2557.520 3000.000 ;
    END
  END la_data_out[69]
  PIN la_data_out[6]
    DIRECTION OUTPUT ;
    USE SIGNAL ;
    ANTENNADIFFAREA 1.386000 ;
    PORT
      LAYER Metal2 ;
        RECT 1425.760 2999.440 1426.320 3000.000 ;
    END
  END la_data_out[6]
  PIN la_data_out[70]
    DIRECTION OUTPUT ;
    USE SIGNAL ;
    ANTENNADIFFAREA 0.290400 ;
    PORT
      LAYER Metal2 ;
        RECT 1909.600 0.000 1910.160 0.560 ;
    END
  END la_data_out[70]
  PIN la_data_out[71]
    DIRECTION OUTPUT ;
    USE SIGNAL ;
    ANTENNADIFFAREA 0.290400 ;
    PORT
      LAYER Metal2 ;
        RECT 2849.280 0.000 2849.840 0.560 ;
    END
  END la_data_out[71]
  PIN la_data_out[72]
    DIRECTION OUTPUT ;
    USE SIGNAL ;
    ANTENNADIFFAREA 0.290400 ;
    PORT
      LAYER Metal2 ;
        RECT 2367.680 2999.440 2368.240 3000.000 ;
    END
  END la_data_out[72]
  PIN la_data_out[73]
    DIRECTION OUTPUT ;
    USE SIGNAL ;
    ANTENNADIFFAREA 0.290400 ;
    PORT
      LAYER Metal2 ;
        RECT 2987.040 0.000 2987.600 0.560 ;
    END
  END la_data_out[73]
  PIN la_data_out[74]
    DIRECTION OUTPUT ;
    USE SIGNAL ;
    ANTENNADIFFAREA 0.290400 ;
    PORT
      LAYER Metal2 ;
        RECT 1952.160 2999.440 1952.720 3000.000 ;
    END
  END la_data_out[74]
  PIN la_data_out[75]
    DIRECTION OUTPUT ;
    USE SIGNAL ;
    ANTENNADIFFAREA 0.290400 ;
    PORT
      LAYER Metal2 ;
        RECT 1983.520 2999.440 1984.080 3000.000 ;
    END
  END la_data_out[75]
  PIN la_data_out[76]
    DIRECTION OUTPUT ;
    USE SIGNAL ;
    ANTENNADIFFAREA 0.290400 ;
    PORT
      LAYER Metal2 ;
        RECT 1910.720 0.000 1911.280 0.560 ;
    END
  END la_data_out[76]
  PIN la_data_out[77]
    DIRECTION OUTPUT ;
    USE SIGNAL ;
    ANTENNADIFFAREA 0.290400 ;
    PORT
      LAYER Metal2 ;
        RECT 2002.560 2999.440 2003.120 3000.000 ;
    END
  END la_data_out[77]
  PIN la_data_out[78]
    DIRECTION OUTPUT ;
    USE SIGNAL ;
    ANTENNADIFFAREA 0.290400 ;
    PORT
      LAYER Metal2 ;
        RECT 1892.800 2999.440 1893.360 3000.000 ;
    END
  END la_data_out[78]
  PIN la_data_out[79]
    DIRECTION OUTPUT ;
    USE SIGNAL ;
    ANTENNADIFFAREA 0.290400 ;
    PORT
      LAYER Metal2 ;
        RECT 1588.160 2999.440 1588.720 3000.000 ;
    END
  END la_data_out[79]
  PIN la_data_out[7]
    DIRECTION OUTPUT ;
    USE SIGNAL ;
    ANTENNADIFFAREA 1.386000 ;
    PORT
      LAYER Metal2 ;
        RECT 1490.720 2999.440 1491.280 3000.000 ;
    END
  END la_data_out[7]
  PIN la_data_out[80]
    DIRECTION OUTPUT ;
    USE SIGNAL ;
    ANTENNADIFFAREA 0.290400 ;
    PORT
      LAYER Metal2 ;
        RECT 1878.240 0.000 1878.800 0.560 ;
    END
  END la_data_out[80]
  PIN la_data_out[81]
    DIRECTION OUTPUT ;
    USE SIGNAL ;
    ANTENNADIFFAREA 0.290400 ;
    PORT
      LAYER Metal2 ;
        RECT 1920.800 2999.440 1921.360 3000.000 ;
    END
  END la_data_out[81]
  PIN la_data_out[82]
    DIRECTION OUTPUT ;
    USE SIGNAL ;
    ANTENNADIFFAREA 0.290400 ;
    PORT
      LAYER Metal2 ;
        RECT 1908.480 0.000 1909.040 0.560 ;
    END
  END la_data_out[82]
  PIN la_data_out[83]
    DIRECTION OUTPUT ;
    USE SIGNAL ;
    ANTENNADIFFAREA 0.290400 ;
    PORT
      LAYER Metal2 ;
        RECT 1906.240 2999.440 1906.800 3000.000 ;
    END
  END la_data_out[83]
  PIN la_data_out[84]
    DIRECTION OUTPUT ;
    USE SIGNAL ;
    ANTENNADIFFAREA 0.290400 ;
    PORT
      LAYER Metal2 ;
        RECT 1929.760 0.000 1930.320 0.560 ;
    END
  END la_data_out[84]
  PIN la_data_out[85]
    DIRECTION OUTPUT ;
    USE SIGNAL ;
    ANTENNADIFFAREA 0.290400 ;
    PORT
      LAYER Metal2 ;
        RECT 2984.800 0.000 2985.360 0.560 ;
    END
  END la_data_out[85]
  PIN la_data_out[86]
    DIRECTION OUTPUT ;
    USE SIGNAL ;
    ANTENNADIFFAREA 0.290400 ;
    PORT
      LAYER Metal2 ;
        RECT 2914.240 0.000 2914.800 0.560 ;
    END
  END la_data_out[86]
  PIN la_data_out[87]
    DIRECTION OUTPUT ;
    USE SIGNAL ;
    ANTENNADIFFAREA 0.290400 ;
    PORT
      LAYER Metal2 ;
        RECT 2630.880 0.000 2631.440 0.560 ;
    END
  END la_data_out[87]
  PIN la_data_out[88]
    DIRECTION OUTPUT ;
    USE SIGNAL ;
    ANTENNADIFFAREA 0.290400 ;
    PORT
      LAYER Metal2 ;
        RECT 2019.360 0.000 2019.920 0.560 ;
    END
  END la_data_out[88]
  PIN la_data_out[89]
    DIRECTION OUTPUT ;
    USE SIGNAL ;
    ANTENNADIFFAREA 0.290400 ;
    PORT
      LAYER Metal2 ;
        RECT 2989.280 0.000 2989.840 0.560 ;
    END
  END la_data_out[89]
  PIN la_data_out[8]
    DIRECTION OUTPUT ;
    USE SIGNAL ;
    ANTENNADIFFAREA 1.386000 ;
    PORT
      LAYER Metal2 ;
        RECT 1513.120 2999.440 1513.680 3000.000 ;
    END
  END la_data_out[8]
  PIN la_data_out[90]
    DIRECTION OUTPUT ;
    USE SIGNAL ;
    ANTENNADIFFAREA 0.290400 ;
    PORT
      LAYER Metal2 ;
        RECT 1204.000 0.000 1204.560 0.560 ;
    END
  END la_data_out[90]
  PIN la_data_out[91]
    DIRECTION OUTPUT ;
    USE SIGNAL ;
    ANTENNADIFFAREA 0.290400 ;
    PORT
      LAYER Metal2 ;
        RECT 1234.240 0.000 1234.800 0.560 ;
    END
  END la_data_out[91]
  PIN la_data_out[92]
    DIRECTION OUTPUT ;
    USE SIGNAL ;
    ANTENNADIFFAREA 0.290400 ;
    PORT
      LAYER Metal2 ;
        RECT 2217.600 2999.440 2218.160 3000.000 ;
    END
  END la_data_out[92]
  PIN la_data_out[93]
    DIRECTION OUTPUT ;
    USE SIGNAL ;
    ANTENNADIFFAREA 0.290400 ;
    PORT
      LAYER Metal2 ;
        RECT 1968.960 0.000 1969.520 0.560 ;
    END
  END la_data_out[93]
  PIN la_data_out[94]
    DIRECTION OUTPUT ;
    USE SIGNAL ;
    ANTENNADIFFAREA 0.290400 ;
    PORT
      LAYER Metal3 ;
        RECT 2999.440 96.320 3000.000 96.880 ;
    END
  END la_data_out[94]
  PIN la_data_out[95]
    DIRECTION OUTPUT ;
    USE SIGNAL ;
    ANTENNADIFFAREA 0.290400 ;
    PORT
      LAYER Metal2 ;
        RECT 2216.480 2999.440 2217.040 3000.000 ;
    END
  END la_data_out[95]
  PIN la_data_out[96]
    DIRECTION OUTPUT ;
    USE SIGNAL ;
    ANTENNADIFFAREA 0.290400 ;
    PORT
      LAYER Metal2 ;
        RECT 2913.120 0.000 2913.680 0.560 ;
    END
  END la_data_out[96]
  PIN la_data_out[97]
    DIRECTION OUTPUT ;
    USE SIGNAL ;
    ANTENNADIFFAREA 0.290400 ;
    PORT
      LAYER Metal2 ;
        RECT 2722.720 0.000 2723.280 0.560 ;
    END
  END la_data_out[97]
  PIN la_data_out[98]
    DIRECTION OUTPUT ;
    USE SIGNAL ;
    ANTENNADIFFAREA 0.290400 ;
    PORT
      LAYER Metal2 ;
        RECT 2591.680 0.000 2592.240 0.560 ;
    END
  END la_data_out[98]
  PIN la_data_out[99]
    DIRECTION OUTPUT ;
    USE SIGNAL ;
    ANTENNADIFFAREA 0.290400 ;
    PORT
      LAYER Metal2 ;
        RECT 2423.680 2999.440 2424.240 3000.000 ;
    END
  END la_data_out[99]
  PIN la_data_out[9]
    DIRECTION OUTPUT ;
    USE SIGNAL ;
    ANTENNADIFFAREA 1.386000 ;
    PORT
      LAYER Metal2 ;
        RECT 1524.320 2999.440 1524.880 3000.000 ;
    END
  END la_data_out[9]
  PIN la_oenb[0]
    DIRECTION INPUT ;
    USE SIGNAL ;
    PORT
      LAYER Metal2 ;
        RECT 161.280 0.000 161.840 0.560 ;
    END
  END la_oenb[0]
  PIN la_oenb[100]
    DIRECTION INPUT ;
    USE SIGNAL ;
    PORT
      LAYER Metal2 ;
        RECT 162.400 0.000 162.960 0.560 ;
    END
  END la_oenb[100]
  PIN la_oenb[101]
    DIRECTION INPUT ;
    USE SIGNAL ;
    PORT
      LAYER Metal2 ;
        RECT 163.520 0.000 164.080 0.560 ;
    END
  END la_oenb[101]
  PIN la_oenb[102]
    DIRECTION INPUT ;
    USE SIGNAL ;
    PORT
      LAYER Metal2 ;
        RECT 164.640 0.000 165.200 0.560 ;
    END
  END la_oenb[102]
  PIN la_oenb[103]
    DIRECTION INPUT ;
    USE SIGNAL ;
    PORT
      LAYER Metal2 ;
        RECT 165.760 0.000 166.320 0.560 ;
    END
  END la_oenb[103]
  PIN la_oenb[104]
    DIRECTION INPUT ;
    USE SIGNAL ;
    PORT
      LAYER Metal2 ;
        RECT 166.880 0.000 167.440 0.560 ;
    END
  END la_oenb[104]
  PIN la_oenb[105]
    DIRECTION INPUT ;
    USE SIGNAL ;
    PORT
      LAYER Metal2 ;
        RECT 168.000 0.000 168.560 0.560 ;
    END
  END la_oenb[105]
  PIN la_oenb[106]
    DIRECTION INPUT ;
    USE SIGNAL ;
    PORT
      LAYER Metal2 ;
        RECT 169.120 0.000 169.680 0.560 ;
    END
  END la_oenb[106]
  PIN la_oenb[107]
    DIRECTION INPUT ;
    USE SIGNAL ;
    PORT
      LAYER Metal2 ;
        RECT 170.240 0.000 170.800 0.560 ;
    END
  END la_oenb[107]
  PIN la_oenb[108]
    DIRECTION INPUT ;
    USE SIGNAL ;
    PORT
      LAYER Metal2 ;
        RECT 171.360 0.000 171.920 0.560 ;
    END
  END la_oenb[108]
  PIN la_oenb[109]
    DIRECTION INPUT ;
    USE SIGNAL ;
    PORT
      LAYER Metal2 ;
        RECT 172.480 0.000 173.040 0.560 ;
    END
  END la_oenb[109]
  PIN la_oenb[10]
    DIRECTION INPUT ;
    USE SIGNAL ;
    PORT
      LAYER Metal2 ;
        RECT 173.600 0.000 174.160 0.560 ;
    END
  END la_oenb[10]
  PIN la_oenb[110]
    DIRECTION INPUT ;
    USE SIGNAL ;
    PORT
      LAYER Metal2 ;
        RECT 174.720 0.000 175.280 0.560 ;
    END
  END la_oenb[110]
  PIN la_oenb[111]
    DIRECTION INPUT ;
    USE SIGNAL ;
    PORT
      LAYER Metal2 ;
        RECT 175.840 0.000 176.400 0.560 ;
    END
  END la_oenb[111]
  PIN la_oenb[112]
    DIRECTION INPUT ;
    USE SIGNAL ;
    PORT
      LAYER Metal2 ;
        RECT 176.960 0.000 177.520 0.560 ;
    END
  END la_oenb[112]
  PIN la_oenb[113]
    DIRECTION INPUT ;
    USE SIGNAL ;
    PORT
      LAYER Metal2 ;
        RECT 178.080 0.000 178.640 0.560 ;
    END
  END la_oenb[113]
  PIN la_oenb[114]
    DIRECTION INPUT ;
    USE SIGNAL ;
    PORT
      LAYER Metal2 ;
        RECT 179.200 0.000 179.760 0.560 ;
    END
  END la_oenb[114]
  PIN la_oenb[115]
    DIRECTION INPUT ;
    USE SIGNAL ;
    PORT
      LAYER Metal2 ;
        RECT 180.320 0.000 180.880 0.560 ;
    END
  END la_oenb[115]
  PIN la_oenb[116]
    DIRECTION INPUT ;
    USE SIGNAL ;
    PORT
      LAYER Metal2 ;
        RECT 181.440 0.000 182.000 0.560 ;
    END
  END la_oenb[116]
  PIN la_oenb[117]
    DIRECTION INPUT ;
    USE SIGNAL ;
    PORT
      LAYER Metal2 ;
        RECT 182.560 0.000 183.120 0.560 ;
    END
  END la_oenb[117]
  PIN la_oenb[118]
    DIRECTION INPUT ;
    USE SIGNAL ;
    PORT
      LAYER Metal2 ;
        RECT 183.680 0.000 184.240 0.560 ;
    END
  END la_oenb[118]
  PIN la_oenb[119]
    DIRECTION INPUT ;
    USE SIGNAL ;
    PORT
      LAYER Metal2 ;
        RECT 184.800 0.000 185.360 0.560 ;
    END
  END la_oenb[119]
  PIN la_oenb[11]
    DIRECTION INPUT ;
    USE SIGNAL ;
    PORT
      LAYER Metal2 ;
        RECT 185.920 0.000 186.480 0.560 ;
    END
  END la_oenb[11]
  PIN la_oenb[120]
    DIRECTION INPUT ;
    USE SIGNAL ;
    PORT
      LAYER Metal2 ;
        RECT 187.040 0.000 187.600 0.560 ;
    END
  END la_oenb[120]
  PIN la_oenb[121]
    DIRECTION INPUT ;
    USE SIGNAL ;
    PORT
      LAYER Metal2 ;
        RECT 188.160 0.000 188.720 0.560 ;
    END
  END la_oenb[121]
  PIN la_oenb[122]
    DIRECTION INPUT ;
    USE SIGNAL ;
    PORT
      LAYER Metal2 ;
        RECT 189.280 0.000 189.840 0.560 ;
    END
  END la_oenb[122]
  PIN la_oenb[123]
    DIRECTION INPUT ;
    USE SIGNAL ;
    PORT
      LAYER Metal2 ;
        RECT 190.400 0.000 190.960 0.560 ;
    END
  END la_oenb[123]
  PIN la_oenb[124]
    DIRECTION INPUT ;
    USE SIGNAL ;
    PORT
      LAYER Metal2 ;
        RECT 191.520 0.000 192.080 0.560 ;
    END
  END la_oenb[124]
  PIN la_oenb[125]
    DIRECTION INPUT ;
    USE SIGNAL ;
    PORT
      LAYER Metal2 ;
        RECT 192.640 0.000 193.200 0.560 ;
    END
  END la_oenb[125]
  PIN la_oenb[126]
    DIRECTION INPUT ;
    USE SIGNAL ;
    PORT
      LAYER Metal2 ;
        RECT 193.760 0.000 194.320 0.560 ;
    END
  END la_oenb[126]
  PIN la_oenb[127]
    DIRECTION INPUT ;
    USE SIGNAL ;
    PORT
      LAYER Metal2 ;
        RECT 194.880 0.000 195.440 0.560 ;
    END
  END la_oenb[127]
  PIN la_oenb[12]
    DIRECTION INPUT ;
    USE SIGNAL ;
    PORT
      LAYER Metal2 ;
        RECT 196.000 0.000 196.560 0.560 ;
    END
  END la_oenb[12]
  PIN la_oenb[13]
    DIRECTION INPUT ;
    USE SIGNAL ;
    PORT
      LAYER Metal2 ;
        RECT 197.120 0.000 197.680 0.560 ;
    END
  END la_oenb[13]
  PIN la_oenb[14]
    DIRECTION INPUT ;
    USE SIGNAL ;
    PORT
      LAYER Metal2 ;
        RECT 198.240 0.000 198.800 0.560 ;
    END
  END la_oenb[14]
  PIN la_oenb[15]
    DIRECTION INPUT ;
    USE SIGNAL ;
    PORT
      LAYER Metal2 ;
        RECT 199.360 0.000 199.920 0.560 ;
    END
  END la_oenb[15]
  PIN la_oenb[16]
    DIRECTION INPUT ;
    USE SIGNAL ;
    PORT
      LAYER Metal2 ;
        RECT 200.480 0.000 201.040 0.560 ;
    END
  END la_oenb[16]
  PIN la_oenb[17]
    DIRECTION INPUT ;
    USE SIGNAL ;
    PORT
      LAYER Metal2 ;
        RECT 201.600 0.000 202.160 0.560 ;
    END
  END la_oenb[17]
  PIN la_oenb[18]
    DIRECTION INPUT ;
    USE SIGNAL ;
    PORT
      LAYER Metal2 ;
        RECT 202.720 0.000 203.280 0.560 ;
    END
  END la_oenb[18]
  PIN la_oenb[19]
    DIRECTION INPUT ;
    USE SIGNAL ;
    PORT
      LAYER Metal2 ;
        RECT 203.840 0.000 204.400 0.560 ;
    END
  END la_oenb[19]
  PIN la_oenb[1]
    DIRECTION INPUT ;
    USE SIGNAL ;
    PORT
      LAYER Metal2 ;
        RECT 204.960 0.000 205.520 0.560 ;
    END
  END la_oenb[1]
  PIN la_oenb[20]
    DIRECTION INPUT ;
    USE SIGNAL ;
    PORT
      LAYER Metal2 ;
        RECT 206.080 0.000 206.640 0.560 ;
    END
  END la_oenb[20]
  PIN la_oenb[21]
    DIRECTION INPUT ;
    USE SIGNAL ;
    PORT
      LAYER Metal2 ;
        RECT 207.200 0.000 207.760 0.560 ;
    END
  END la_oenb[21]
  PIN la_oenb[22]
    DIRECTION INPUT ;
    USE SIGNAL ;
    PORT
      LAYER Metal2 ;
        RECT 208.320 0.000 208.880 0.560 ;
    END
  END la_oenb[22]
  PIN la_oenb[23]
    DIRECTION INPUT ;
    USE SIGNAL ;
    PORT
      LAYER Metal2 ;
        RECT 209.440 0.000 210.000 0.560 ;
    END
  END la_oenb[23]
  PIN la_oenb[24]
    DIRECTION INPUT ;
    USE SIGNAL ;
    PORT
      LAYER Metal2 ;
        RECT 210.560 0.000 211.120 0.560 ;
    END
  END la_oenb[24]
  PIN la_oenb[25]
    DIRECTION INPUT ;
    USE SIGNAL ;
    PORT
      LAYER Metal2 ;
        RECT 211.680 0.000 212.240 0.560 ;
    END
  END la_oenb[25]
  PIN la_oenb[26]
    DIRECTION INPUT ;
    USE SIGNAL ;
    PORT
      LAYER Metal2 ;
        RECT 212.800 0.000 213.360 0.560 ;
    END
  END la_oenb[26]
  PIN la_oenb[27]
    DIRECTION INPUT ;
    USE SIGNAL ;
    PORT
      LAYER Metal2 ;
        RECT 213.920 0.000 214.480 0.560 ;
    END
  END la_oenb[27]
  PIN la_oenb[28]
    DIRECTION INPUT ;
    USE SIGNAL ;
    PORT
      LAYER Metal2 ;
        RECT 215.040 0.000 215.600 0.560 ;
    END
  END la_oenb[28]
  PIN la_oenb[29]
    DIRECTION INPUT ;
    USE SIGNAL ;
    PORT
      LAYER Metal2 ;
        RECT 216.160 0.000 216.720 0.560 ;
    END
  END la_oenb[29]
  PIN la_oenb[2]
    DIRECTION INPUT ;
    USE SIGNAL ;
    PORT
      LAYER Metal2 ;
        RECT 217.280 0.000 217.840 0.560 ;
    END
  END la_oenb[2]
  PIN la_oenb[30]
    DIRECTION INPUT ;
    USE SIGNAL ;
    PORT
      LAYER Metal2 ;
        RECT 218.400 0.000 218.960 0.560 ;
    END
  END la_oenb[30]
  PIN la_oenb[31]
    DIRECTION INPUT ;
    USE SIGNAL ;
    PORT
      LAYER Metal2 ;
        RECT 219.520 0.000 220.080 0.560 ;
    END
  END la_oenb[31]
  PIN la_oenb[32]
    DIRECTION INPUT ;
    USE SIGNAL ;
    PORT
      LAYER Metal2 ;
        RECT 220.640 0.000 221.200 0.560 ;
    END
  END la_oenb[32]
  PIN la_oenb[33]
    DIRECTION INPUT ;
    USE SIGNAL ;
    PORT
      LAYER Metal2 ;
        RECT 221.760 0.000 222.320 0.560 ;
    END
  END la_oenb[33]
  PIN la_oenb[34]
    DIRECTION INPUT ;
    USE SIGNAL ;
    PORT
      LAYER Metal2 ;
        RECT 222.880 0.000 223.440 0.560 ;
    END
  END la_oenb[34]
  PIN la_oenb[35]
    DIRECTION INPUT ;
    USE SIGNAL ;
    PORT
      LAYER Metal2 ;
        RECT 224.000 0.000 224.560 0.560 ;
    END
  END la_oenb[35]
  PIN la_oenb[36]
    DIRECTION INPUT ;
    USE SIGNAL ;
    PORT
      LAYER Metal2 ;
        RECT 225.120 0.000 225.680 0.560 ;
    END
  END la_oenb[36]
  PIN la_oenb[37]
    DIRECTION INPUT ;
    USE SIGNAL ;
    PORT
      LAYER Metal2 ;
        RECT 226.240 0.000 226.800 0.560 ;
    END
  END la_oenb[37]
  PIN la_oenb[38]
    DIRECTION INPUT ;
    USE SIGNAL ;
    PORT
      LAYER Metal2 ;
        RECT 227.360 0.000 227.920 0.560 ;
    END
  END la_oenb[38]
  PIN la_oenb[39]
    DIRECTION INPUT ;
    USE SIGNAL ;
    PORT
      LAYER Metal2 ;
        RECT 228.480 0.000 229.040 0.560 ;
    END
  END la_oenb[39]
  PIN la_oenb[3]
    DIRECTION INPUT ;
    USE SIGNAL ;
    PORT
      LAYER Metal2 ;
        RECT 229.600 0.000 230.160 0.560 ;
    END
  END la_oenb[3]
  PIN la_oenb[40]
    DIRECTION INPUT ;
    USE SIGNAL ;
    PORT
      LAYER Metal2 ;
        RECT 230.720 0.000 231.280 0.560 ;
    END
  END la_oenb[40]
  PIN la_oenb[41]
    DIRECTION INPUT ;
    USE SIGNAL ;
    PORT
      LAYER Metal2 ;
        RECT 231.840 0.000 232.400 0.560 ;
    END
  END la_oenb[41]
  PIN la_oenb[42]
    DIRECTION INPUT ;
    USE SIGNAL ;
    PORT
      LAYER Metal2 ;
        RECT 232.960 0.000 233.520 0.560 ;
    END
  END la_oenb[42]
  PIN la_oenb[43]
    DIRECTION INPUT ;
    USE SIGNAL ;
    PORT
      LAYER Metal2 ;
        RECT 234.080 0.000 234.640 0.560 ;
    END
  END la_oenb[43]
  PIN la_oenb[44]
    DIRECTION INPUT ;
    USE SIGNAL ;
    PORT
      LAYER Metal2 ;
        RECT 235.200 0.000 235.760 0.560 ;
    END
  END la_oenb[44]
  PIN la_oenb[45]
    DIRECTION INPUT ;
    USE SIGNAL ;
    PORT
      LAYER Metal2 ;
        RECT 236.320 0.000 236.880 0.560 ;
    END
  END la_oenb[45]
  PIN la_oenb[46]
    DIRECTION INPUT ;
    USE SIGNAL ;
    PORT
      LAYER Metal2 ;
        RECT 237.440 0.000 238.000 0.560 ;
    END
  END la_oenb[46]
  PIN la_oenb[47]
    DIRECTION INPUT ;
    USE SIGNAL ;
    PORT
      LAYER Metal2 ;
        RECT 238.560 0.000 239.120 0.560 ;
    END
  END la_oenb[47]
  PIN la_oenb[48]
    DIRECTION INPUT ;
    USE SIGNAL ;
    PORT
      LAYER Metal2 ;
        RECT 239.680 0.000 240.240 0.560 ;
    END
  END la_oenb[48]
  PIN la_oenb[49]
    DIRECTION INPUT ;
    USE SIGNAL ;
    PORT
      LAYER Metal2 ;
        RECT 240.800 0.000 241.360 0.560 ;
    END
  END la_oenb[49]
  PIN la_oenb[4]
    DIRECTION INPUT ;
    USE SIGNAL ;
    PORT
      LAYER Metal2 ;
        RECT 241.920 0.000 242.480 0.560 ;
    END
  END la_oenb[4]
  PIN la_oenb[50]
    DIRECTION INPUT ;
    USE SIGNAL ;
    PORT
      LAYER Metal2 ;
        RECT 243.040 0.000 243.600 0.560 ;
    END
  END la_oenb[50]
  PIN la_oenb[51]
    DIRECTION INPUT ;
    USE SIGNAL ;
    PORT
      LAYER Metal2 ;
        RECT 244.160 0.000 244.720 0.560 ;
    END
  END la_oenb[51]
  PIN la_oenb[52]
    DIRECTION INPUT ;
    USE SIGNAL ;
    PORT
      LAYER Metal2 ;
        RECT 245.280 0.000 245.840 0.560 ;
    END
  END la_oenb[52]
  PIN la_oenb[53]
    DIRECTION INPUT ;
    USE SIGNAL ;
    PORT
      LAYER Metal2 ;
        RECT 246.400 0.000 246.960 0.560 ;
    END
  END la_oenb[53]
  PIN la_oenb[54]
    DIRECTION INPUT ;
    USE SIGNAL ;
    PORT
      LAYER Metal2 ;
        RECT 247.520 0.000 248.080 0.560 ;
    END
  END la_oenb[54]
  PIN la_oenb[55]
    DIRECTION INPUT ;
    USE SIGNAL ;
    PORT
      LAYER Metal2 ;
        RECT 248.640 0.000 249.200 0.560 ;
    END
  END la_oenb[55]
  PIN la_oenb[56]
    DIRECTION INPUT ;
    USE SIGNAL ;
    PORT
      LAYER Metal2 ;
        RECT 249.760 0.000 250.320 0.560 ;
    END
  END la_oenb[56]
  PIN la_oenb[57]
    DIRECTION INPUT ;
    USE SIGNAL ;
    PORT
      LAYER Metal2 ;
        RECT 250.880 0.000 251.440 0.560 ;
    END
  END la_oenb[57]
  PIN la_oenb[58]
    DIRECTION INPUT ;
    USE SIGNAL ;
    PORT
      LAYER Metal2 ;
        RECT 252.000 0.000 252.560 0.560 ;
    END
  END la_oenb[58]
  PIN la_oenb[59]
    DIRECTION INPUT ;
    USE SIGNAL ;
    PORT
      LAYER Metal2 ;
        RECT 253.120 0.000 253.680 0.560 ;
    END
  END la_oenb[59]
  PIN la_oenb[5]
    DIRECTION INPUT ;
    USE SIGNAL ;
    PORT
      LAYER Metal2 ;
        RECT 254.240 0.000 254.800 0.560 ;
    END
  END la_oenb[5]
  PIN la_oenb[60]
    DIRECTION INPUT ;
    USE SIGNAL ;
    PORT
      LAYER Metal2 ;
        RECT 255.360 0.000 255.920 0.560 ;
    END
  END la_oenb[60]
  PIN la_oenb[61]
    DIRECTION INPUT ;
    USE SIGNAL ;
    PORT
      LAYER Metal2 ;
        RECT 256.480 0.000 257.040 0.560 ;
    END
  END la_oenb[61]
  PIN la_oenb[62]
    DIRECTION INPUT ;
    USE SIGNAL ;
    PORT
      LAYER Metal2 ;
        RECT 257.600 0.000 258.160 0.560 ;
    END
  END la_oenb[62]
  PIN la_oenb[63]
    DIRECTION INPUT ;
    USE SIGNAL ;
    PORT
      LAYER Metal2 ;
        RECT 258.720 0.000 259.280 0.560 ;
    END
  END la_oenb[63]
  PIN la_oenb[64]
    DIRECTION INPUT ;
    USE SIGNAL ;
    PORT
      LAYER Metal2 ;
        RECT 259.840 0.000 260.400 0.560 ;
    END
  END la_oenb[64]
  PIN la_oenb[65]
    DIRECTION INPUT ;
    USE SIGNAL ;
    PORT
      LAYER Metal2 ;
        RECT 260.960 0.000 261.520 0.560 ;
    END
  END la_oenb[65]
  PIN la_oenb[66]
    DIRECTION INPUT ;
    USE SIGNAL ;
    PORT
      LAYER Metal2 ;
        RECT 262.080 0.000 262.640 0.560 ;
    END
  END la_oenb[66]
  PIN la_oenb[67]
    DIRECTION INPUT ;
    USE SIGNAL ;
    PORT
      LAYER Metal2 ;
        RECT 263.200 0.000 263.760 0.560 ;
    END
  END la_oenb[67]
  PIN la_oenb[68]
    DIRECTION INPUT ;
    USE SIGNAL ;
    PORT
      LAYER Metal2 ;
        RECT 264.320 0.000 264.880 0.560 ;
    END
  END la_oenb[68]
  PIN la_oenb[69]
    DIRECTION INPUT ;
    USE SIGNAL ;
    PORT
      LAYER Metal2 ;
        RECT 265.440 0.000 266.000 0.560 ;
    END
  END la_oenb[69]
  PIN la_oenb[6]
    DIRECTION INPUT ;
    USE SIGNAL ;
    PORT
      LAYER Metal2 ;
        RECT 266.560 0.000 267.120 0.560 ;
    END
  END la_oenb[6]
  PIN la_oenb[70]
    DIRECTION INPUT ;
    USE SIGNAL ;
    PORT
      LAYER Metal2 ;
        RECT 267.680 0.000 268.240 0.560 ;
    END
  END la_oenb[70]
  PIN la_oenb[71]
    DIRECTION INPUT ;
    USE SIGNAL ;
    PORT
      LAYER Metal2 ;
        RECT 268.800 0.000 269.360 0.560 ;
    END
  END la_oenb[71]
  PIN la_oenb[72]
    DIRECTION INPUT ;
    USE SIGNAL ;
    PORT
      LAYER Metal2 ;
        RECT 269.920 0.000 270.480 0.560 ;
    END
  END la_oenb[72]
  PIN la_oenb[73]
    DIRECTION INPUT ;
    USE SIGNAL ;
    PORT
      LAYER Metal2 ;
        RECT 271.040 0.000 271.600 0.560 ;
    END
  END la_oenb[73]
  PIN la_oenb[74]
    DIRECTION INPUT ;
    USE SIGNAL ;
    PORT
      LAYER Metal2 ;
        RECT 272.160 0.000 272.720 0.560 ;
    END
  END la_oenb[74]
  PIN la_oenb[75]
    DIRECTION INPUT ;
    USE SIGNAL ;
    PORT
      LAYER Metal2 ;
        RECT 273.280 0.000 273.840 0.560 ;
    END
  END la_oenb[75]
  PIN la_oenb[76]
    DIRECTION INPUT ;
    USE SIGNAL ;
    PORT
      LAYER Metal2 ;
        RECT 274.400 0.000 274.960 0.560 ;
    END
  END la_oenb[76]
  PIN la_oenb[77]
    DIRECTION INPUT ;
    USE SIGNAL ;
    PORT
      LAYER Metal2 ;
        RECT 275.520 0.000 276.080 0.560 ;
    END
  END la_oenb[77]
  PIN la_oenb[78]
    DIRECTION INPUT ;
    USE SIGNAL ;
    PORT
      LAYER Metal2 ;
        RECT 276.640 0.000 277.200 0.560 ;
    END
  END la_oenb[78]
  PIN la_oenb[79]
    DIRECTION INPUT ;
    USE SIGNAL ;
    PORT
      LAYER Metal2 ;
        RECT 277.760 0.000 278.320 0.560 ;
    END
  END la_oenb[79]
  PIN la_oenb[7]
    DIRECTION INPUT ;
    USE SIGNAL ;
    PORT
      LAYER Metal2 ;
        RECT 278.880 0.000 279.440 0.560 ;
    END
  END la_oenb[7]
  PIN la_oenb[80]
    DIRECTION INPUT ;
    USE SIGNAL ;
    PORT
      LAYER Metal2 ;
        RECT 280.000 0.000 280.560 0.560 ;
    END
  END la_oenb[80]
  PIN la_oenb[81]
    DIRECTION INPUT ;
    USE SIGNAL ;
    PORT
      LAYER Metal2 ;
        RECT 281.120 0.000 281.680 0.560 ;
    END
  END la_oenb[81]
  PIN la_oenb[82]
    DIRECTION INPUT ;
    USE SIGNAL ;
    PORT
      LAYER Metal2 ;
        RECT 282.240 0.000 282.800 0.560 ;
    END
  END la_oenb[82]
  PIN la_oenb[83]
    DIRECTION INPUT ;
    USE SIGNAL ;
    PORT
      LAYER Metal2 ;
        RECT 283.360 0.000 283.920 0.560 ;
    END
  END la_oenb[83]
  PIN la_oenb[84]
    DIRECTION INPUT ;
    USE SIGNAL ;
    PORT
      LAYER Metal2 ;
        RECT 284.480 0.000 285.040 0.560 ;
    END
  END la_oenb[84]
  PIN la_oenb[85]
    DIRECTION INPUT ;
    USE SIGNAL ;
    PORT
      LAYER Metal2 ;
        RECT 285.600 0.000 286.160 0.560 ;
    END
  END la_oenb[85]
  PIN la_oenb[86]
    DIRECTION INPUT ;
    USE SIGNAL ;
    PORT
      LAYER Metal2 ;
        RECT 286.720 0.000 287.280 0.560 ;
    END
  END la_oenb[86]
  PIN la_oenb[87]
    DIRECTION INPUT ;
    USE SIGNAL ;
    PORT
      LAYER Metal2 ;
        RECT 287.840 0.000 288.400 0.560 ;
    END
  END la_oenb[87]
  PIN la_oenb[88]
    DIRECTION INPUT ;
    USE SIGNAL ;
    PORT
      LAYER Metal2 ;
        RECT 288.960 0.000 289.520 0.560 ;
    END
  END la_oenb[88]
  PIN la_oenb[89]
    DIRECTION INPUT ;
    USE SIGNAL ;
    PORT
      LAYER Metal2 ;
        RECT 290.080 0.000 290.640 0.560 ;
    END
  END la_oenb[89]
  PIN la_oenb[8]
    DIRECTION INPUT ;
    USE SIGNAL ;
    PORT
      LAYER Metal2 ;
        RECT 291.200 0.000 291.760 0.560 ;
    END
  END la_oenb[8]
  PIN la_oenb[90]
    DIRECTION INPUT ;
    USE SIGNAL ;
    PORT
      LAYER Metal2 ;
        RECT 292.320 0.000 292.880 0.560 ;
    END
  END la_oenb[90]
  PIN la_oenb[91]
    DIRECTION INPUT ;
    USE SIGNAL ;
    PORT
      LAYER Metal2 ;
        RECT 293.440 0.000 294.000 0.560 ;
    END
  END la_oenb[91]
  PIN la_oenb[92]
    DIRECTION INPUT ;
    USE SIGNAL ;
    PORT
      LAYER Metal2 ;
        RECT 294.560 0.000 295.120 0.560 ;
    END
  END la_oenb[92]
  PIN la_oenb[93]
    DIRECTION INPUT ;
    USE SIGNAL ;
    PORT
      LAYER Metal2 ;
        RECT 295.680 0.000 296.240 0.560 ;
    END
  END la_oenb[93]
  PIN la_oenb[94]
    DIRECTION INPUT ;
    USE SIGNAL ;
    PORT
      LAYER Metal2 ;
        RECT 296.800 0.000 297.360 0.560 ;
    END
  END la_oenb[94]
  PIN la_oenb[95]
    DIRECTION INPUT ;
    USE SIGNAL ;
    PORT
      LAYER Metal2 ;
        RECT 297.920 0.000 298.480 0.560 ;
    END
  END la_oenb[95]
  PIN la_oenb[96]
    DIRECTION INPUT ;
    USE SIGNAL ;
    PORT
      LAYER Metal2 ;
        RECT 299.040 0.000 299.600 0.560 ;
    END
  END la_oenb[96]
  PIN la_oenb[97]
    DIRECTION INPUT ;
    USE SIGNAL ;
    PORT
      LAYER Metal2 ;
        RECT 300.160 0.000 300.720 0.560 ;
    END
  END la_oenb[97]
  PIN la_oenb[98]
    DIRECTION INPUT ;
    USE SIGNAL ;
    PORT
      LAYER Metal2 ;
        RECT 301.280 0.000 301.840 0.560 ;
    END
  END la_oenb[98]
  PIN la_oenb[99]
    DIRECTION INPUT ;
    USE SIGNAL ;
    PORT
      LAYER Metal2 ;
        RECT 302.400 0.000 302.960 0.560 ;
    END
  END la_oenb[99]
  PIN la_oenb[9]
    DIRECTION INPUT ;
    USE SIGNAL ;
    PORT
      LAYER Metal2 ;
        RECT 303.520 0.000 304.080 0.560 ;
    END
  END la_oenb[9]
  PIN wb_clk_i
    DIRECTION INPUT ;
    USE SIGNAL ;
    ANTENNAGATEAREA 13.530000 ;
    PORT
      LAYER Metal2 ;
        RECT 304.640 0.000 305.200 0.560 ;
    END
  END wb_clk_i
  PIN wb_rst_i
    DIRECTION INPUT ;
    USE SIGNAL ;
    ANTENNAGATEAREA 0.396000 ;
    PORT
      LAYER Metal2 ;
        RECT 2054.080 2999.440 2054.640 3000.000 ;
    END
  END wb_rst_i
  PIN wbs_ack_o
    DIRECTION OUTPUT ;
    USE SIGNAL ;
    ANTENNADIFFAREA 1.386000 ;
    PORT
      LAYER Metal2 ;
        RECT 1303.680 2999.440 1304.240 3000.000 ;
    END
  END wbs_ack_o
  PIN wbs_adr_i[0]
    DIRECTION INPUT ;
    USE SIGNAL ;
    ANTENNAGATEAREA 0.396000 ;
    PORT
      LAYER Metal2 ;
        RECT 1196.160 2999.440 1196.720 3000.000 ;
    END
  END wbs_adr_i[0]
  PIN wbs_adr_i[10]
    DIRECTION INPUT ;
    USE SIGNAL ;
    PORT
      LAYER Metal2 ;
        RECT 305.760 0.000 306.320 0.560 ;
    END
  END wbs_adr_i[10]
  PIN wbs_adr_i[11]
    DIRECTION INPUT ;
    USE SIGNAL ;
    PORT
      LAYER Metal2 ;
        RECT 306.880 0.000 307.440 0.560 ;
    END
  END wbs_adr_i[11]
  PIN wbs_adr_i[12]
    DIRECTION INPUT ;
    USE SIGNAL ;
    PORT
      LAYER Metal2 ;
        RECT 308.000 0.000 308.560 0.560 ;
    END
  END wbs_adr_i[12]
  PIN wbs_adr_i[13]
    DIRECTION INPUT ;
    USE SIGNAL ;
    PORT
      LAYER Metal2 ;
        RECT 309.120 0.000 309.680 0.560 ;
    END
  END wbs_adr_i[13]
  PIN wbs_adr_i[14]
    DIRECTION INPUT ;
    USE SIGNAL ;
    PORT
      LAYER Metal2 ;
        RECT 310.240 0.000 310.800 0.560 ;
    END
  END wbs_adr_i[14]
  PIN wbs_adr_i[15]
    DIRECTION INPUT ;
    USE SIGNAL ;
    PORT
      LAYER Metal2 ;
        RECT 311.360 0.000 311.920 0.560 ;
    END
  END wbs_adr_i[15]
  PIN wbs_adr_i[16]
    DIRECTION INPUT ;
    USE SIGNAL ;
    PORT
      LAYER Metal2 ;
        RECT 312.480 0.000 313.040 0.560 ;
    END
  END wbs_adr_i[16]
  PIN wbs_adr_i[17]
    DIRECTION INPUT ;
    USE SIGNAL ;
    PORT
      LAYER Metal2 ;
        RECT 313.600 0.000 314.160 0.560 ;
    END
  END wbs_adr_i[17]
  PIN wbs_adr_i[18]
    DIRECTION INPUT ;
    USE SIGNAL ;
    PORT
      LAYER Metal2 ;
        RECT 314.720 0.000 315.280 0.560 ;
    END
  END wbs_adr_i[18]
  PIN wbs_adr_i[19]
    DIRECTION INPUT ;
    USE SIGNAL ;
    PORT
      LAYER Metal2 ;
        RECT 315.840 0.000 316.400 0.560 ;
    END
  END wbs_adr_i[19]
  PIN wbs_adr_i[1]
    DIRECTION INPUT ;
    USE SIGNAL ;
    ANTENNAGATEAREA 0.396000 ;
    PORT
      LAYER Metal2 ;
        RECT 1195.040 2999.440 1195.600 3000.000 ;
    END
  END wbs_adr_i[1]
  PIN wbs_adr_i[20]
    DIRECTION INPUT ;
    USE SIGNAL ;
    PORT
      LAYER Metal2 ;
        RECT 316.960 0.000 317.520 0.560 ;
    END
  END wbs_adr_i[20]
  PIN wbs_adr_i[21]
    DIRECTION INPUT ;
    USE SIGNAL ;
    PORT
      LAYER Metal2 ;
        RECT 318.080 0.000 318.640 0.560 ;
    END
  END wbs_adr_i[21]
  PIN wbs_adr_i[22]
    DIRECTION INPUT ;
    USE SIGNAL ;
    PORT
      LAYER Metal2 ;
        RECT 319.200 0.000 319.760 0.560 ;
    END
  END wbs_adr_i[22]
  PIN wbs_adr_i[23]
    DIRECTION INPUT ;
    USE SIGNAL ;
    PORT
      LAYER Metal2 ;
        RECT 320.320 0.000 320.880 0.560 ;
    END
  END wbs_adr_i[23]
  PIN wbs_adr_i[24]
    DIRECTION INPUT ;
    USE SIGNAL ;
    PORT
      LAYER Metal2 ;
        RECT 321.440 0.000 322.000 0.560 ;
    END
  END wbs_adr_i[24]
  PIN wbs_adr_i[25]
    DIRECTION INPUT ;
    USE SIGNAL ;
    PORT
      LAYER Metal2 ;
        RECT 322.560 0.000 323.120 0.560 ;
    END
  END wbs_adr_i[25]
  PIN wbs_adr_i[26]
    DIRECTION INPUT ;
    USE SIGNAL ;
    PORT
      LAYER Metal2 ;
        RECT 323.680 0.000 324.240 0.560 ;
    END
  END wbs_adr_i[26]
  PIN wbs_adr_i[27]
    DIRECTION INPUT ;
    USE SIGNAL ;
    PORT
      LAYER Metal2 ;
        RECT 324.800 0.000 325.360 0.560 ;
    END
  END wbs_adr_i[27]
  PIN wbs_adr_i[28]
    DIRECTION INPUT ;
    USE SIGNAL ;
    PORT
      LAYER Metal2 ;
        RECT 325.920 0.000 326.480 0.560 ;
    END
  END wbs_adr_i[28]
  PIN wbs_adr_i[29]
    DIRECTION INPUT ;
    USE SIGNAL ;
    PORT
      LAYER Metal2 ;
        RECT 327.040 0.000 327.600 0.560 ;
    END
  END wbs_adr_i[29]
  PIN wbs_adr_i[2]
    DIRECTION INPUT ;
    USE SIGNAL ;
    ANTENNAGATEAREA 0.396000 ;
    PORT
      LAYER Metal2 ;
        RECT 1282.400 2999.440 1282.960 3000.000 ;
    END
  END wbs_adr_i[2]
  PIN wbs_adr_i[30]
    DIRECTION INPUT ;
    USE SIGNAL ;
    PORT
      LAYER Metal2 ;
        RECT 328.160 0.000 328.720 0.560 ;
    END
  END wbs_adr_i[30]
  PIN wbs_adr_i[31]
    DIRECTION INPUT ;
    USE SIGNAL ;
    PORT
      LAYER Metal2 ;
        RECT 329.280 0.000 329.840 0.560 ;
    END
  END wbs_adr_i[31]
  PIN wbs_adr_i[3]
    DIRECTION INPUT ;
    USE SIGNAL ;
    ANTENNAGATEAREA 0.396000 ;
    PORT
      LAYER Metal2 ;
        RECT 1268.960 2999.440 1269.520 3000.000 ;
    END
  END wbs_adr_i[3]
  PIN wbs_adr_i[4]
    DIRECTION INPUT ;
    USE SIGNAL ;
    ANTENNAGATEAREA 0.396000 ;
    PORT
      LAYER Metal2 ;
        RECT 1206.240 2999.440 1206.800 3000.000 ;
    END
  END wbs_adr_i[4]
  PIN wbs_adr_i[5]
    DIRECTION INPUT ;
    USE SIGNAL ;
    ANTENNAGATEAREA 0.396000 ;
    PORT
      LAYER Metal2 ;
        RECT 1266.720 2999.440 1267.280 3000.000 ;
    END
  END wbs_adr_i[5]
  PIN wbs_adr_i[6]
    DIRECTION INPUT ;
    USE SIGNAL ;
    ANTENNAGATEAREA 0.396000 ;
    PORT
      LAYER Metal2 ;
        RECT 1265.600 2999.440 1266.160 3000.000 ;
    END
  END wbs_adr_i[6]
  PIN wbs_adr_i[7]
    DIRECTION INPUT ;
    USE SIGNAL ;
    ANTENNAGATEAREA 0.396000 ;
    PORT
      LAYER Metal2 ;
        RECT 1267.840 2999.440 1268.400 3000.000 ;
    END
  END wbs_adr_i[7]
  PIN wbs_adr_i[8]
    DIRECTION INPUT ;
    USE SIGNAL ;
    PORT
      LAYER Metal2 ;
        RECT 330.400 0.000 330.960 0.560 ;
    END
  END wbs_adr_i[8]
  PIN wbs_adr_i[9]
    DIRECTION INPUT ;
    USE SIGNAL ;
    PORT
      LAYER Metal2 ;
        RECT 331.520 0.000 332.080 0.560 ;
    END
  END wbs_adr_i[9]
  PIN wbs_cyc_i
    DIRECTION INPUT ;
    USE SIGNAL ;
    ANTENNAGATEAREA 0.396000 ;
    PORT
      LAYER Metal2 ;
        RECT 1310.400 2999.440 1310.960 3000.000 ;
    END
  END wbs_cyc_i
  PIN wbs_dat_i[0]
    DIRECTION INPUT ;
    USE SIGNAL ;
    ANTENNAGATEAREA 0.396000 ;
    PORT
      LAYER Metal2 ;
        RECT 1342.880 2999.440 1343.440 3000.000 ;
    END
  END wbs_dat_i[0]
  PIN wbs_dat_i[10]
    DIRECTION INPUT ;
    USE SIGNAL ;
    ANTENNAGATEAREA 0.396000 ;
    PORT
      LAYER Metal2 ;
        RECT 1420.160 2999.440 1420.720 3000.000 ;
    END
  END wbs_dat_i[10]
  PIN wbs_dat_i[11]
    DIRECTION INPUT ;
    USE SIGNAL ;
    ANTENNAGATEAREA 0.396000 ;
    PORT
      LAYER Metal2 ;
        RECT 1444.800 2999.440 1445.360 3000.000 ;
    END
  END wbs_dat_i[11]
  PIN wbs_dat_i[12]
    DIRECTION INPUT ;
    USE SIGNAL ;
    ANTENNAGATEAREA 0.396000 ;
    PORT
      LAYER Metal2 ;
        RECT 1452.640 2999.440 1453.200 3000.000 ;
    END
  END wbs_dat_i[12]
  PIN wbs_dat_i[13]
    DIRECTION INPUT ;
    USE SIGNAL ;
    ANTENNAGATEAREA 0.396000 ;
    PORT
      LAYER Metal2 ;
        RECT 1459.360 2999.440 1459.920 3000.000 ;
    END
  END wbs_dat_i[13]
  PIN wbs_dat_i[14]
    DIRECTION INPUT ;
    USE SIGNAL ;
    ANTENNAGATEAREA 0.396000 ;
    PORT
      LAYER Metal2 ;
        RECT 1497.440 2999.440 1498.000 3000.000 ;
    END
  END wbs_dat_i[14]
  PIN wbs_dat_i[15]
    DIRECTION INPUT ;
    USE SIGNAL ;
    ANTENNAGATEAREA 0.396000 ;
    PORT
      LAYER Metal2 ;
        RECT 1499.680 2999.440 1500.240 3000.000 ;
    END
  END wbs_dat_i[15]
  PIN wbs_dat_i[16]
    DIRECTION INPUT ;
    USE SIGNAL ;
    PORT
      LAYER Metal2 ;
        RECT 332.640 0.000 333.200 0.560 ;
    END
  END wbs_dat_i[16]
  PIN wbs_dat_i[17]
    DIRECTION INPUT ;
    USE SIGNAL ;
    PORT
      LAYER Metal2 ;
        RECT 333.760 0.000 334.320 0.560 ;
    END
  END wbs_dat_i[17]
  PIN wbs_dat_i[18]
    DIRECTION INPUT ;
    USE SIGNAL ;
    PORT
      LAYER Metal2 ;
        RECT 334.880 0.000 335.440 0.560 ;
    END
  END wbs_dat_i[18]
  PIN wbs_dat_i[19]
    DIRECTION INPUT ;
    USE SIGNAL ;
    PORT
      LAYER Metal2 ;
        RECT 336.000 0.000 336.560 0.560 ;
    END
  END wbs_dat_i[19]
  PIN wbs_dat_i[1]
    DIRECTION INPUT ;
    USE SIGNAL ;
    ANTENNAGATEAREA 0.396000 ;
    PORT
      LAYER Metal2 ;
        RECT 1359.680 2999.440 1360.240 3000.000 ;
    END
  END wbs_dat_i[1]
  PIN wbs_dat_i[20]
    DIRECTION INPUT ;
    USE SIGNAL ;
    PORT
      LAYER Metal2 ;
        RECT 337.120 0.000 337.680 0.560 ;
    END
  END wbs_dat_i[20]
  PIN wbs_dat_i[21]
    DIRECTION INPUT ;
    USE SIGNAL ;
    PORT
      LAYER Metal2 ;
        RECT 338.240 0.000 338.800 0.560 ;
    END
  END wbs_dat_i[21]
  PIN wbs_dat_i[22]
    DIRECTION INPUT ;
    USE SIGNAL ;
    PORT
      LAYER Metal2 ;
        RECT 339.360 0.000 339.920 0.560 ;
    END
  END wbs_dat_i[22]
  PIN wbs_dat_i[23]
    DIRECTION INPUT ;
    USE SIGNAL ;
    PORT
      LAYER Metal2 ;
        RECT 340.480 0.000 341.040 0.560 ;
    END
  END wbs_dat_i[23]
  PIN wbs_dat_i[24]
    DIRECTION INPUT ;
    USE SIGNAL ;
    PORT
      LAYER Metal2 ;
        RECT 341.600 0.000 342.160 0.560 ;
    END
  END wbs_dat_i[24]
  PIN wbs_dat_i[25]
    DIRECTION INPUT ;
    USE SIGNAL ;
    PORT
      LAYER Metal2 ;
        RECT 342.720 0.000 343.280 0.560 ;
    END
  END wbs_dat_i[25]
  PIN wbs_dat_i[26]
    DIRECTION INPUT ;
    USE SIGNAL ;
    PORT
      LAYER Metal2 ;
        RECT 343.840 0.000 344.400 0.560 ;
    END
  END wbs_dat_i[26]
  PIN wbs_dat_i[27]
    DIRECTION INPUT ;
    USE SIGNAL ;
    PORT
      LAYER Metal2 ;
        RECT 344.960 0.000 345.520 0.560 ;
    END
  END wbs_dat_i[27]
  PIN wbs_dat_i[28]
    DIRECTION INPUT ;
    USE SIGNAL ;
    PORT
      LAYER Metal2 ;
        RECT 346.080 0.000 346.640 0.560 ;
    END
  END wbs_dat_i[28]
  PIN wbs_dat_i[29]
    DIRECTION INPUT ;
    USE SIGNAL ;
    PORT
      LAYER Metal2 ;
        RECT 347.200 0.000 347.760 0.560 ;
    END
  END wbs_dat_i[29]
  PIN wbs_dat_i[2]
    DIRECTION INPUT ;
    USE SIGNAL ;
    ANTENNAGATEAREA 0.396000 ;
    PORT
      LAYER Metal2 ;
        RECT 1326.080 2999.440 1326.640 3000.000 ;
    END
  END wbs_dat_i[2]
  PIN wbs_dat_i[30]
    DIRECTION INPUT ;
    USE SIGNAL ;
    PORT
      LAYER Metal2 ;
        RECT 348.320 0.000 348.880 0.560 ;
    END
  END wbs_dat_i[30]
  PIN wbs_dat_i[31]
    DIRECTION INPUT ;
    USE SIGNAL ;
    PORT
      LAYER Metal2 ;
        RECT 349.440 0.000 350.000 0.560 ;
    END
  END wbs_dat_i[31]
  PIN wbs_dat_i[3]
    DIRECTION INPUT ;
    USE SIGNAL ;
    ANTENNAGATEAREA 0.396000 ;
    PORT
      LAYER Metal2 ;
        RECT 1356.320 2999.440 1356.880 3000.000 ;
    END
  END wbs_dat_i[3]
  PIN wbs_dat_i[4]
    DIRECTION INPUT ;
    USE SIGNAL ;
    ANTENNAGATEAREA 0.396000 ;
    PORT
      LAYER Metal2 ;
        RECT 1338.400 2999.440 1338.960 3000.000 ;
    END
  END wbs_dat_i[4]
  PIN wbs_dat_i[5]
    DIRECTION INPUT ;
    USE SIGNAL ;
    ANTENNAGATEAREA 0.396000 ;
    PORT
      LAYER Metal2 ;
        RECT 1317.120 2999.440 1317.680 3000.000 ;
    END
  END wbs_dat_i[5]
  PIN wbs_dat_i[6]
    DIRECTION INPUT ;
    USE SIGNAL ;
    ANTENNAGATEAREA 0.396000 ;
    PORT
      LAYER Metal2 ;
        RECT 1352.960 2999.440 1353.520 3000.000 ;
    END
  END wbs_dat_i[6]
  PIN wbs_dat_i[7]
    DIRECTION INPUT ;
    USE SIGNAL ;
    ANTENNAGATEAREA 0.396000 ;
    PORT
      LAYER Metal2 ;
        RECT 1336.160 2999.440 1336.720 3000.000 ;
    END
  END wbs_dat_i[7]
  PIN wbs_dat_i[8]
    DIRECTION INPUT ;
    USE SIGNAL ;
    ANTENNAGATEAREA 0.396000 ;
    PORT
      LAYER Metal2 ;
        RECT 1375.360 2999.440 1375.920 3000.000 ;
    END
  END wbs_dat_i[8]
  PIN wbs_dat_i[9]
    DIRECTION INPUT ;
    USE SIGNAL ;
    ANTENNAGATEAREA 0.396000 ;
    PORT
      LAYER Metal2 ;
        RECT 1383.200 2999.440 1383.760 3000.000 ;
    END
  END wbs_dat_i[9]
  PIN wbs_dat_o[0]
    DIRECTION OUTPUT ;
    USE SIGNAL ;
    ANTENNADIFFAREA 1.386000 ;
    PORT
      LAYER Metal2 ;
        RECT 1363.040 2999.440 1363.600 3000.000 ;
    END
  END wbs_dat_o[0]
  PIN wbs_dat_o[10]
    DIRECTION OUTPUT ;
    USE SIGNAL ;
    ANTENNADIFFAREA 1.386000 ;
    PORT
      LAYER Metal2 ;
        RECT 1438.080 2999.440 1438.640 3000.000 ;
    END
  END wbs_dat_o[10]
  PIN wbs_dat_o[11]
    DIRECTION OUTPUT ;
    USE SIGNAL ;
    ANTENNADIFFAREA 1.386000 ;
    PORT
      LAYER Metal2 ;
        RECT 1441.440 2999.440 1442.000 3000.000 ;
    END
  END wbs_dat_o[11]
  PIN wbs_dat_o[12]
    DIRECTION OUTPUT ;
    USE SIGNAL ;
    ANTENNADIFFAREA 1.386000 ;
    PORT
      LAYER Metal2 ;
        RECT 1458.240 2999.440 1458.800 3000.000 ;
    END
  END wbs_dat_o[12]
  PIN wbs_dat_o[13]
    DIRECTION OUTPUT ;
    USE SIGNAL ;
    ANTENNADIFFAREA 1.386000 ;
    PORT
      LAYER Metal2 ;
        RECT 1457.120 2999.440 1457.680 3000.000 ;
    END
  END wbs_dat_o[13]
  PIN wbs_dat_o[14]
    DIRECTION OUTPUT ;
    USE SIGNAL ;
    ANTENNADIFFAREA 1.386000 ;
    PORT
      LAYER Metal2 ;
        RECT 1488.480 2999.440 1489.040 3000.000 ;
    END
  END wbs_dat_o[14]
  PIN wbs_dat_o[15]
    DIRECTION OUTPUT ;
    USE SIGNAL ;
    ANTENNADIFFAREA 1.386000 ;
    PORT
      LAYER Metal2 ;
        RECT 1481.760 2999.440 1482.320 3000.000 ;
    END
  END wbs_dat_o[15]
  PIN wbs_dat_o[16]
    DIRECTION OUTPUT ;
    USE SIGNAL ;
    ANTENNADIFFAREA 0.290400 ;
    PORT
      LAYER Metal2 ;
        RECT 2522.240 2999.440 2522.800 3000.000 ;
    END
  END wbs_dat_o[16]
  PIN wbs_dat_o[17]
    DIRECTION OUTPUT ;
    USE SIGNAL ;
    ANTENNADIFFAREA 0.290400 ;
    PORT
      LAYER Metal2 ;
        RECT 2982.560 0.000 2983.120 0.560 ;
    END
  END wbs_dat_o[17]
  PIN wbs_dat_o[18]
    DIRECTION OUTPUT ;
    USE SIGNAL ;
    ANTENNADIFFAREA 0.290400 ;
    PORT
      LAYER Metal2 ;
        RECT 2503.200 2999.440 2503.760 3000.000 ;
    END
  END wbs_dat_o[18]
  PIN wbs_dat_o[19]
    DIRECTION OUTPUT ;
    USE SIGNAL ;
    ANTENNADIFFAREA 0.290400 ;
    PORT
      LAYER Metal2 ;
        RECT 2504.320 2999.440 2504.880 3000.000 ;
    END
  END wbs_dat_o[19]
  PIN wbs_dat_o[1]
    DIRECTION OUTPUT ;
    USE SIGNAL ;
    ANTENNADIFFAREA 1.386000 ;
    PORT
      LAYER Metal2 ;
        RECT 1421.280 2999.440 1421.840 3000.000 ;
    END
  END wbs_dat_o[1]
  PIN wbs_dat_o[20]
    DIRECTION OUTPUT ;
    USE SIGNAL ;
    ANTENNADIFFAREA 0.290400 ;
    PORT
      LAYER Metal3 ;
        RECT 2999.440 2079.840 3000.000 2080.400 ;
    END
  END wbs_dat_o[20]
  PIN wbs_dat_o[21]
    DIRECTION OUTPUT ;
    USE SIGNAL ;
    ANTENNADIFFAREA 0.290400 ;
    PORT
      LAYER Metal2 ;
        RECT 2185.120 2999.440 2185.680 3000.000 ;
    END
  END wbs_dat_o[21]
  PIN wbs_dat_o[22]
    DIRECTION OUTPUT ;
    USE SIGNAL ;
    ANTENNADIFFAREA 0.290400 ;
    PORT
      LAYER Metal3 ;
        RECT 2999.440 1682.240 3000.000 1682.800 ;
    END
  END wbs_dat_o[22]
  PIN wbs_dat_o[23]
    DIRECTION OUTPUT ;
    USE SIGNAL ;
    ANTENNADIFFAREA 0.290400 ;
    PORT
      LAYER Metal2 ;
        RECT 2929.920 0.000 2930.480 0.560 ;
    END
  END wbs_dat_o[23]
  PIN wbs_dat_o[24]
    DIRECTION OUTPUT ;
    USE SIGNAL ;
    ANTENNADIFFAREA 0.290400 ;
    PORT
      LAYER Metal2 ;
        RECT 2102.240 2999.440 2102.800 3000.000 ;
    END
  END wbs_dat_o[24]
  PIN wbs_dat_o[25]
    DIRECTION OUTPUT ;
    USE SIGNAL ;
    ANTENNADIFFAREA 0.290400 ;
    PORT
      LAYER Metal2 ;
        RECT 2980.320 0.000 2980.880 0.560 ;
    END
  END wbs_dat_o[25]
  PIN wbs_dat_o[26]
    DIRECTION OUTPUT ;
    USE SIGNAL ;
    ANTENNADIFFAREA 0.290400 ;
    PORT
      LAYER Metal2 ;
        RECT 2272.480 2999.440 2273.040 3000.000 ;
    END
  END wbs_dat_o[26]
  PIN wbs_dat_o[27]
    DIRECTION OUTPUT ;
    USE SIGNAL ;
    ANTENNADIFFAREA 0.290400 ;
    PORT
      LAYER Metal3 ;
        RECT 2999.440 1553.440 3000.000 1554.000 ;
    END
  END wbs_dat_o[27]
  PIN wbs_dat_o[28]
    DIRECTION OUTPUT ;
    USE SIGNAL ;
    ANTENNADIFFAREA 0.290400 ;
    PORT
      LAYER Metal2 ;
        RECT 2112.320 2999.440 2112.880 3000.000 ;
    END
  END wbs_dat_o[28]
  PIN wbs_dat_o[29]
    DIRECTION OUTPUT ;
    USE SIGNAL ;
    ANTENNADIFFAREA 0.290400 ;
    PORT
      LAYER Metal3 ;
        RECT 2999.440 2214.240 3000.000 2214.800 ;
    END
  END wbs_dat_o[29]
  PIN wbs_dat_o[2]
    DIRECTION OUTPUT ;
    USE SIGNAL ;
    ANTENNADIFFAREA 1.386000 ;
    PORT
      LAYER Metal2 ;
        RECT 1419.040 2999.440 1419.600 3000.000 ;
    END
  END wbs_dat_o[2]
  PIN wbs_dat_o[30]
    DIRECTION OUTPUT ;
    USE SIGNAL ;
    ANTENNADIFFAREA 0.290400 ;
    PORT
      LAYER Metal2 ;
        RECT 2238.880 2999.440 2239.440 3000.000 ;
    END
  END wbs_dat_o[30]
  PIN wbs_dat_o[31]
    DIRECTION OUTPUT ;
    USE SIGNAL ;
    ANTENNADIFFAREA 0.290400 ;
    PORT
      LAYER Metal3 ;
        RECT 2999.440 101.920 3000.000 102.480 ;
    END
  END wbs_dat_o[31]
  PIN wbs_dat_o[3]
    DIRECTION OUTPUT ;
    USE SIGNAL ;
    ANTENNADIFFAREA 1.386000 ;
    PORT
      LAYER Metal2 ;
        RECT 1398.880 2999.440 1399.440 3000.000 ;
    END
  END wbs_dat_o[3]
  PIN wbs_dat_o[4]
    DIRECTION OUTPUT ;
    USE SIGNAL ;
    ANTENNADIFFAREA 1.386000 ;
    PORT
      LAYER Metal2 ;
        RECT 1397.760 2999.440 1398.320 3000.000 ;
    END
  END wbs_dat_o[4]
  PIN wbs_dat_o[5]
    DIRECTION OUTPUT ;
    USE SIGNAL ;
    ANTENNADIFFAREA 1.386000 ;
    PORT
      LAYER Metal2 ;
        RECT 1374.240 2999.440 1374.800 3000.000 ;
    END
  END wbs_dat_o[5]
  PIN wbs_dat_o[6]
    DIRECTION OUTPUT ;
    USE SIGNAL ;
    ANTENNADIFFAREA 1.386000 ;
    PORT
      LAYER Metal2 ;
        RECT 1413.440 2999.440 1414.000 3000.000 ;
    END
  END wbs_dat_o[6]
  PIN wbs_dat_o[7]
    DIRECTION OUTPUT ;
    USE SIGNAL ;
    ANTENNADIFFAREA 1.386000 ;
    PORT
      LAYER Metal2 ;
        RECT 1436.960 2999.440 1437.520 3000.000 ;
    END
  END wbs_dat_o[7]
  PIN wbs_dat_o[8]
    DIRECTION OUTPUT ;
    USE SIGNAL ;
    ANTENNADIFFAREA 1.386000 ;
    PORT
      LAYER Metal2 ;
        RECT 1417.920 2999.440 1418.480 3000.000 ;
    END
  END wbs_dat_o[8]
  PIN wbs_dat_o[9]
    DIRECTION OUTPUT ;
    USE SIGNAL ;
    ANTENNADIFFAREA 1.386000 ;
    PORT
      LAYER Metal2 ;
        RECT 1411.200 2999.440 1411.760 3000.000 ;
    END
  END wbs_dat_o[9]
  PIN wbs_sel_i[0]
    DIRECTION INPUT ;
    USE SIGNAL ;
    ANTENNAGATEAREA 0.396000 ;
    PORT
      LAYER Metal2 ;
        RECT 1308.160 2999.440 1308.720 3000.000 ;
    END
  END wbs_sel_i[0]
  PIN wbs_sel_i[1]
    DIRECTION INPUT ;
    USE SIGNAL ;
    ANTENNAGATEAREA 0.396000 ;
    PORT
      LAYER Metal2 ;
        RECT 1361.920 2999.440 1362.480 3000.000 ;
    END
  END wbs_sel_i[1]
  PIN wbs_sel_i[2]
    DIRECTION INPUT ;
    USE SIGNAL ;
    PORT
      LAYER Metal2 ;
        RECT 350.560 0.000 351.120 0.560 ;
    END
  END wbs_sel_i[2]
  PIN wbs_sel_i[3]
    DIRECTION INPUT ;
    USE SIGNAL ;
    PORT
      LAYER Metal2 ;
        RECT 351.680 0.000 352.240 0.560 ;
    END
  END wbs_sel_i[3]
  PIN wbs_stb_i
    DIRECTION INPUT ;
    USE SIGNAL ;
    ANTENNAGATEAREA 0.396000 ;
    PORT
      LAYER Metal2 ;
        RECT 1309.280 2999.440 1309.840 3000.000 ;
    END
  END wbs_stb_i
  PIN wbs_we_i
    DIRECTION INPUT ;
    USE SIGNAL ;
    ANTENNAGATEAREA 0.396000 ;
    PORT
      LAYER Metal2 ;
        RECT 1360.800 2999.440 1361.360 3000.000 ;
    END
  END wbs_we_i
  OBS
      LAYER Nwell ;
        RECT 3.790 19.730 2996.130 2979.070 ;
      LAYER Metal1 ;
        RECT 6.720 19.710 2993.200 2979.090 ;
      LAYER Metal2 ;
        RECT 7.980 2999.140 129.620 2999.780 ;
        RECT 130.780 2999.140 1194.740 2999.780 ;
        RECT 1197.020 2999.140 1205.940 2999.780 ;
        RECT 1207.100 2999.140 1265.300 2999.780 ;
        RECT 1269.820 2999.140 1282.100 2999.780 ;
        RECT 1283.260 2999.140 1303.380 2999.780 ;
        RECT 1304.540 2999.140 1307.860 2999.780 ;
        RECT 1311.260 2999.140 1316.820 2999.780 ;
        RECT 1317.980 2999.140 1325.780 2999.780 ;
        RECT 1326.940 2999.140 1335.860 2999.780 ;
        RECT 1337.020 2999.140 1338.100 2999.780 ;
        RECT 1339.260 2999.140 1342.580 2999.780 ;
        RECT 1344.860 2999.140 1347.060 2999.780 ;
        RECT 1348.220 2999.140 1349.300 2999.780 ;
        RECT 1350.460 2999.140 1352.660 2999.780 ;
        RECT 1353.820 2999.140 1356.020 2999.780 ;
        RECT 1357.180 2999.140 1359.380 2999.780 ;
        RECT 1367.260 2999.140 1373.940 2999.780 ;
        RECT 1376.220 2999.140 1382.900 2999.780 ;
        RECT 1384.060 2999.140 1386.260 2999.780 ;
        RECT 1387.420 2999.140 1397.460 2999.780 ;
        RECT 1399.740 2999.140 1410.900 2999.780 ;
        RECT 1412.060 2999.140 1413.140 2999.780 ;
        RECT 1414.300 2999.140 1417.620 2999.780 ;
        RECT 1422.140 2999.140 1425.460 2999.780 ;
        RECT 1431.100 2999.140 1436.660 2999.780 ;
        RECT 1438.940 2999.140 1441.140 2999.780 ;
        RECT 1442.300 2999.140 1444.500 2999.780 ;
        RECT 1446.780 2999.140 1452.340 2999.780 ;
        RECT 1453.500 2999.140 1456.820 2999.780 ;
        RECT 1460.220 2999.140 1481.460 2999.780 ;
        RECT 1482.620 2999.140 1488.180 2999.780 ;
        RECT 1489.340 2999.140 1490.420 2999.780 ;
        RECT 1491.580 2999.140 1497.140 2999.780 ;
        RECT 1498.300 2999.140 1499.380 2999.780 ;
        RECT 1500.540 2999.140 1512.820 2999.780 ;
        RECT 1513.980 2999.140 1524.020 2999.780 ;
        RECT 1525.180 2999.140 1558.740 2999.780 ;
        RECT 1559.900 2999.140 1576.660 2999.780 ;
        RECT 1577.820 2999.140 1578.900 2999.780 ;
        RECT 1580.060 2999.140 1587.860 2999.780 ;
        RECT 1589.020 2999.140 1616.980 2999.780 ;
        RECT 1618.140 2999.140 1619.220 2999.780 ;
        RECT 1620.380 2999.140 1679.700 2999.780 ;
        RECT 1681.980 2999.140 1683.060 2999.780 ;
        RECT 1684.220 2999.140 1687.540 2999.780 ;
        RECT 1688.700 2999.140 1725.620 2999.780 ;
        RECT 1726.780 2999.140 1778.260 2999.780 ;
        RECT 1779.420 2999.140 1868.980 2999.780 ;
        RECT 1870.140 2999.140 1873.460 2999.780 ;
        RECT 1874.620 2999.140 1884.660 2999.780 ;
        RECT 1885.820 2999.140 1892.500 2999.780 ;
        RECT 1893.660 2999.140 1899.220 2999.780 ;
        RECT 1900.380 2999.140 1905.940 2999.780 ;
        RECT 1907.100 2999.140 1920.500 2999.780 ;
        RECT 1921.660 2999.140 1951.860 2999.780 ;
        RECT 1953.020 2999.140 1972.020 2999.780 ;
        RECT 1973.180 2999.140 1982.100 2999.780 ;
        RECT 1984.380 2999.140 2002.260 2999.780 ;
        RECT 2003.420 2999.140 2039.220 2999.780 ;
        RECT 2040.380 2999.140 2042.580 2999.780 ;
        RECT 2043.740 2999.140 2047.060 2999.780 ;
        RECT 2048.220 2999.140 2051.540 2999.780 ;
        RECT 2052.700 2999.140 2053.780 2999.780 ;
        RECT 2054.940 2999.140 2060.500 2999.780 ;
        RECT 2061.660 2999.140 2063.860 2999.780 ;
        RECT 2065.020 2999.140 2066.100 2999.780 ;
        RECT 2067.260 2999.140 2069.460 2999.780 ;
        RECT 2072.860 2999.140 2101.940 2999.780 ;
        RECT 2103.100 2999.140 2112.020 2999.780 ;
        RECT 2113.180 2999.140 2115.380 2999.780 ;
        RECT 2116.540 2999.140 2117.620 2999.780 ;
        RECT 2118.780 2999.140 2132.180 2999.780 ;
        RECT 2133.340 2999.140 2153.460 2999.780 ;
        RECT 2154.620 2999.140 2160.180 2999.780 ;
        RECT 2161.340 2999.140 2162.420 2999.780 ;
        RECT 2163.580 2999.140 2172.500 2999.780 ;
        RECT 2173.660 2999.140 2180.340 2999.780 ;
        RECT 2181.500 2999.140 2184.820 2999.780 ;
        RECT 2185.980 2999.140 2203.860 2999.780 ;
        RECT 2205.020 2999.140 2216.180 2999.780 ;
        RECT 2218.460 2999.140 2238.580 2999.780 ;
        RECT 2239.740 2999.140 2268.820 2999.780 ;
        RECT 2269.980 2999.140 2272.180 2999.780 ;
        RECT 2273.340 2999.140 2294.580 2999.780 ;
        RECT 2295.740 2999.140 2316.980 2999.780 ;
        RECT 2318.140 2999.140 2327.060 2999.780 ;
        RECT 2328.220 2999.140 2355.060 2999.780 ;
        RECT 2356.220 2999.140 2367.380 2999.780 ;
        RECT 2368.540 2999.140 2386.420 2999.780 ;
        RECT 2387.580 2999.140 2390.900 2999.780 ;
        RECT 2392.060 2999.140 2423.380 2999.780 ;
        RECT 2424.540 2999.140 2434.580 2999.780 ;
        RECT 2435.740 2999.140 2472.660 2999.780 ;
        RECT 2473.820 2999.140 2502.900 2999.780 ;
        RECT 2505.180 2999.140 2507.380 2999.780 ;
        RECT 2508.540 2999.140 2521.940 2999.780 ;
        RECT 2523.100 2999.140 2536.500 2999.780 ;
        RECT 2537.660 2999.140 2556.660 2999.780 ;
        RECT 2557.820 2999.140 2991.940 2999.780 ;
        RECT 7.980 0.860 2991.940 2999.140 ;
        RECT 352.540 0.140 661.620 0.860 ;
        RECT 662.780 0.140 1203.700 0.860 ;
        RECT 1204.860 0.140 1233.940 0.860 ;
        RECT 1235.100 0.140 1387.380 0.860 ;
        RECT 1388.540 0.140 1643.860 0.860 ;
        RECT 1645.020 0.140 1784.980 0.860 ;
        RECT 1786.140 0.140 1792.820 0.860 ;
        RECT 1793.980 0.140 1834.260 0.860 ;
        RECT 1835.420 0.140 1853.300 0.860 ;
        RECT 1854.460 0.140 1870.100 0.860 ;
        RECT 1871.260 0.140 1877.940 0.860 ;
        RECT 1879.100 0.140 1888.020 0.860 ;
        RECT 1889.180 0.140 1908.180 0.860 ;
        RECT 1913.820 0.140 1921.620 0.860 ;
        RECT 1925.020 0.140 1929.460 0.860 ;
        RECT 1930.620 0.140 1932.820 0.860 ;
        RECT 1933.980 0.140 1968.660 0.860 ;
        RECT 1969.820 0.140 1973.140 0.860 ;
        RECT 1975.420 0.140 2019.060 0.860 ;
        RECT 2020.220 0.140 2156.820 0.860 ;
        RECT 2159.100 0.140 2217.300 0.860 ;
        RECT 2218.460 0.140 2250.900 0.860 ;
        RECT 2252.060 0.140 2269.940 0.860 ;
        RECT 2271.100 0.140 2306.900 0.860 ;
        RECT 2308.060 0.140 2328.180 0.860 ;
        RECT 2329.340 0.140 2331.540 0.860 ;
        RECT 2332.700 0.140 2365.140 0.860 ;
        RECT 2366.300 0.140 2369.620 0.860 ;
        RECT 2370.780 0.140 2416.660 0.860 ;
        RECT 2417.820 0.140 2458.100 0.860 ;
        RECT 2459.260 0.140 2497.300 0.860 ;
        RECT 2498.460 0.140 2508.500 0.860 ;
        RECT 2509.660 0.140 2591.380 0.860 ;
        RECT 2592.540 0.140 2610.420 0.860 ;
        RECT 2611.580 0.140 2613.780 0.860 ;
        RECT 2614.940 0.140 2630.580 0.860 ;
        RECT 2631.740 0.140 2697.780 0.860 ;
        RECT 2698.940 0.140 2722.420 0.860 ;
        RECT 2723.580 0.140 2767.220 0.860 ;
        RECT 2768.380 0.140 2843.380 0.860 ;
        RECT 2844.540 0.140 2848.980 0.860 ;
        RECT 2850.140 0.140 2912.820 0.860 ;
        RECT 2915.100 0.140 2927.380 0.860 ;
        RECT 2928.540 0.140 2929.620 0.860 ;
        RECT 2931.900 0.140 2944.180 0.860 ;
        RECT 2945.340 0.140 2950.900 0.860 ;
        RECT 2952.060 0.140 2958.740 0.860 ;
        RECT 2961.020 0.140 2963.220 0.860 ;
        RECT 2964.380 0.140 2965.460 0.860 ;
        RECT 2966.620 0.140 2973.300 0.860 ;
        RECT 2974.460 0.140 2978.900 0.860 ;
        RECT 2991.260 0.140 2991.940 0.860 ;
      LAYER Metal3 ;
        RECT 0.560 2835.580 2999.440 2999.220 ;
        RECT 0.560 2834.420 2999.140 2835.580 ;
        RECT 0.560 2832.220 2999.440 2834.420 ;
        RECT 0.560 2831.060 2999.140 2832.220 ;
        RECT 0.560 2712.380 2999.440 2831.060 ;
        RECT 0.560 2711.220 2999.140 2712.380 ;
        RECT 0.560 2602.620 2999.440 2711.220 ;
        RECT 0.560 2601.460 2999.140 2602.620 ;
        RECT 0.560 2352.860 2999.440 2601.460 ;
        RECT 0.560 2351.700 2999.140 2352.860 ;
        RECT 0.560 2215.100 2999.440 2351.700 ;
        RECT 0.560 2213.940 2999.140 2215.100 ;
        RECT 0.560 2080.700 2999.440 2213.940 ;
        RECT 0.560 2079.540 2999.140 2080.700 ;
        RECT 0.560 2021.340 2999.440 2079.540 ;
        RECT 0.560 2020.180 2999.140 2021.340 ;
        RECT 0.560 1684.220 2999.440 2020.180 ;
        RECT 0.560 1681.940 2999.140 1684.220 ;
        RECT 0.560 1599.100 2999.440 1681.940 ;
        RECT 0.560 1597.940 2999.140 1599.100 ;
        RECT 0.560 1586.780 2999.440 1597.940 ;
        RECT 0.860 1585.620 2999.440 1586.780 ;
        RECT 0.560 1554.300 2999.440 1585.620 ;
        RECT 0.560 1553.140 2999.140 1554.300 ;
        RECT 0.560 1500.540 2999.440 1553.140 ;
        RECT 0.560 1499.380 2999.140 1500.540 ;
        RECT 0.560 1438.940 2999.440 1499.380 ;
        RECT 0.560 1437.780 2999.140 1438.940 ;
        RECT 0.560 1408.700 2999.440 1437.780 ;
        RECT 0.560 1407.540 2999.140 1408.700 ;
        RECT 0.560 1302.300 2999.440 1407.540 ;
        RECT 0.560 1301.140 2999.140 1302.300 ;
        RECT 0.560 1269.820 2999.440 1301.140 ;
        RECT 0.560 1268.660 2999.140 1269.820 ;
        RECT 0.560 869.980 2999.440 1268.660 ;
        RECT 0.560 868.820 2999.140 869.980 ;
        RECT 0.560 102.780 2999.440 868.820 ;
        RECT 0.560 101.620 2999.140 102.780 ;
        RECT 0.560 97.180 2999.440 101.620 ;
        RECT 0.560 96.020 2999.140 97.180 ;
        RECT 0.560 72.540 2999.440 96.020 ;
        RECT 0.560 71.380 2999.140 72.540 ;
        RECT 0.560 63.580 2999.440 71.380 ;
        RECT 0.560 62.420 2999.140 63.580 ;
        RECT 0.560 61.340 2999.440 62.420 ;
        RECT 0.560 60.180 2999.140 61.340 ;
        RECT 0.560 0.700 2999.440 60.180 ;
      LAYER Metal4 ;
        RECT 317.660 19.560 329.140 2966.790 ;
        RECT 331.340 19.560 332.440 2966.790 ;
        RECT 334.640 19.560 482.740 2966.790 ;
        RECT 484.940 19.560 486.040 2966.790 ;
        RECT 488.240 19.560 636.340 2966.790 ;
        RECT 638.540 19.560 639.640 2966.790 ;
        RECT 641.840 19.560 789.940 2966.790 ;
        RECT 792.140 19.560 793.240 2966.790 ;
        RECT 795.440 19.560 943.540 2966.790 ;
        RECT 945.740 19.560 946.840 2966.790 ;
        RECT 949.040 19.560 1097.140 2966.790 ;
        RECT 1099.340 19.560 1100.440 2966.790 ;
        RECT 1102.640 19.560 1250.740 2966.790 ;
        RECT 1252.940 19.560 1254.040 2966.790 ;
        RECT 1256.240 19.560 1404.340 2966.790 ;
        RECT 1406.540 19.560 1407.640 2966.790 ;
        RECT 1409.840 19.560 1557.940 2966.790 ;
        RECT 1560.140 19.560 1561.240 2966.790 ;
        RECT 1563.440 19.560 1711.540 2966.790 ;
        RECT 1713.740 19.560 1714.840 2966.790 ;
        RECT 1717.040 19.560 1865.140 2966.790 ;
        RECT 1867.340 19.560 1868.440 2966.790 ;
        RECT 1870.640 19.560 2018.740 2966.790 ;
        RECT 2020.940 19.560 2022.040 2966.790 ;
        RECT 2024.240 19.560 2172.340 2966.790 ;
        RECT 2174.540 19.560 2175.640 2966.790 ;
        RECT 2177.840 19.560 2325.940 2966.790 ;
        RECT 2328.140 19.560 2329.240 2966.790 ;
        RECT 2331.440 19.560 2479.540 2966.790 ;
        RECT 2481.740 19.560 2482.840 2966.790 ;
        RECT 2485.040 19.560 2633.140 2966.790 ;
        RECT 2635.340 19.560 2636.440 2966.790 ;
        RECT 2638.640 19.560 2786.740 2966.790 ;
        RECT 2788.940 19.560 2790.040 2966.790 ;
        RECT 2792.240 19.560 2940.340 2966.790 ;
        RECT 2942.540 19.560 2943.640 2966.790 ;
        RECT 2945.840 19.560 2988.580 2966.790 ;
        RECT 317.660 7.930 2988.580 19.560 ;
  END
END senseedge_top
END LIBRARY

